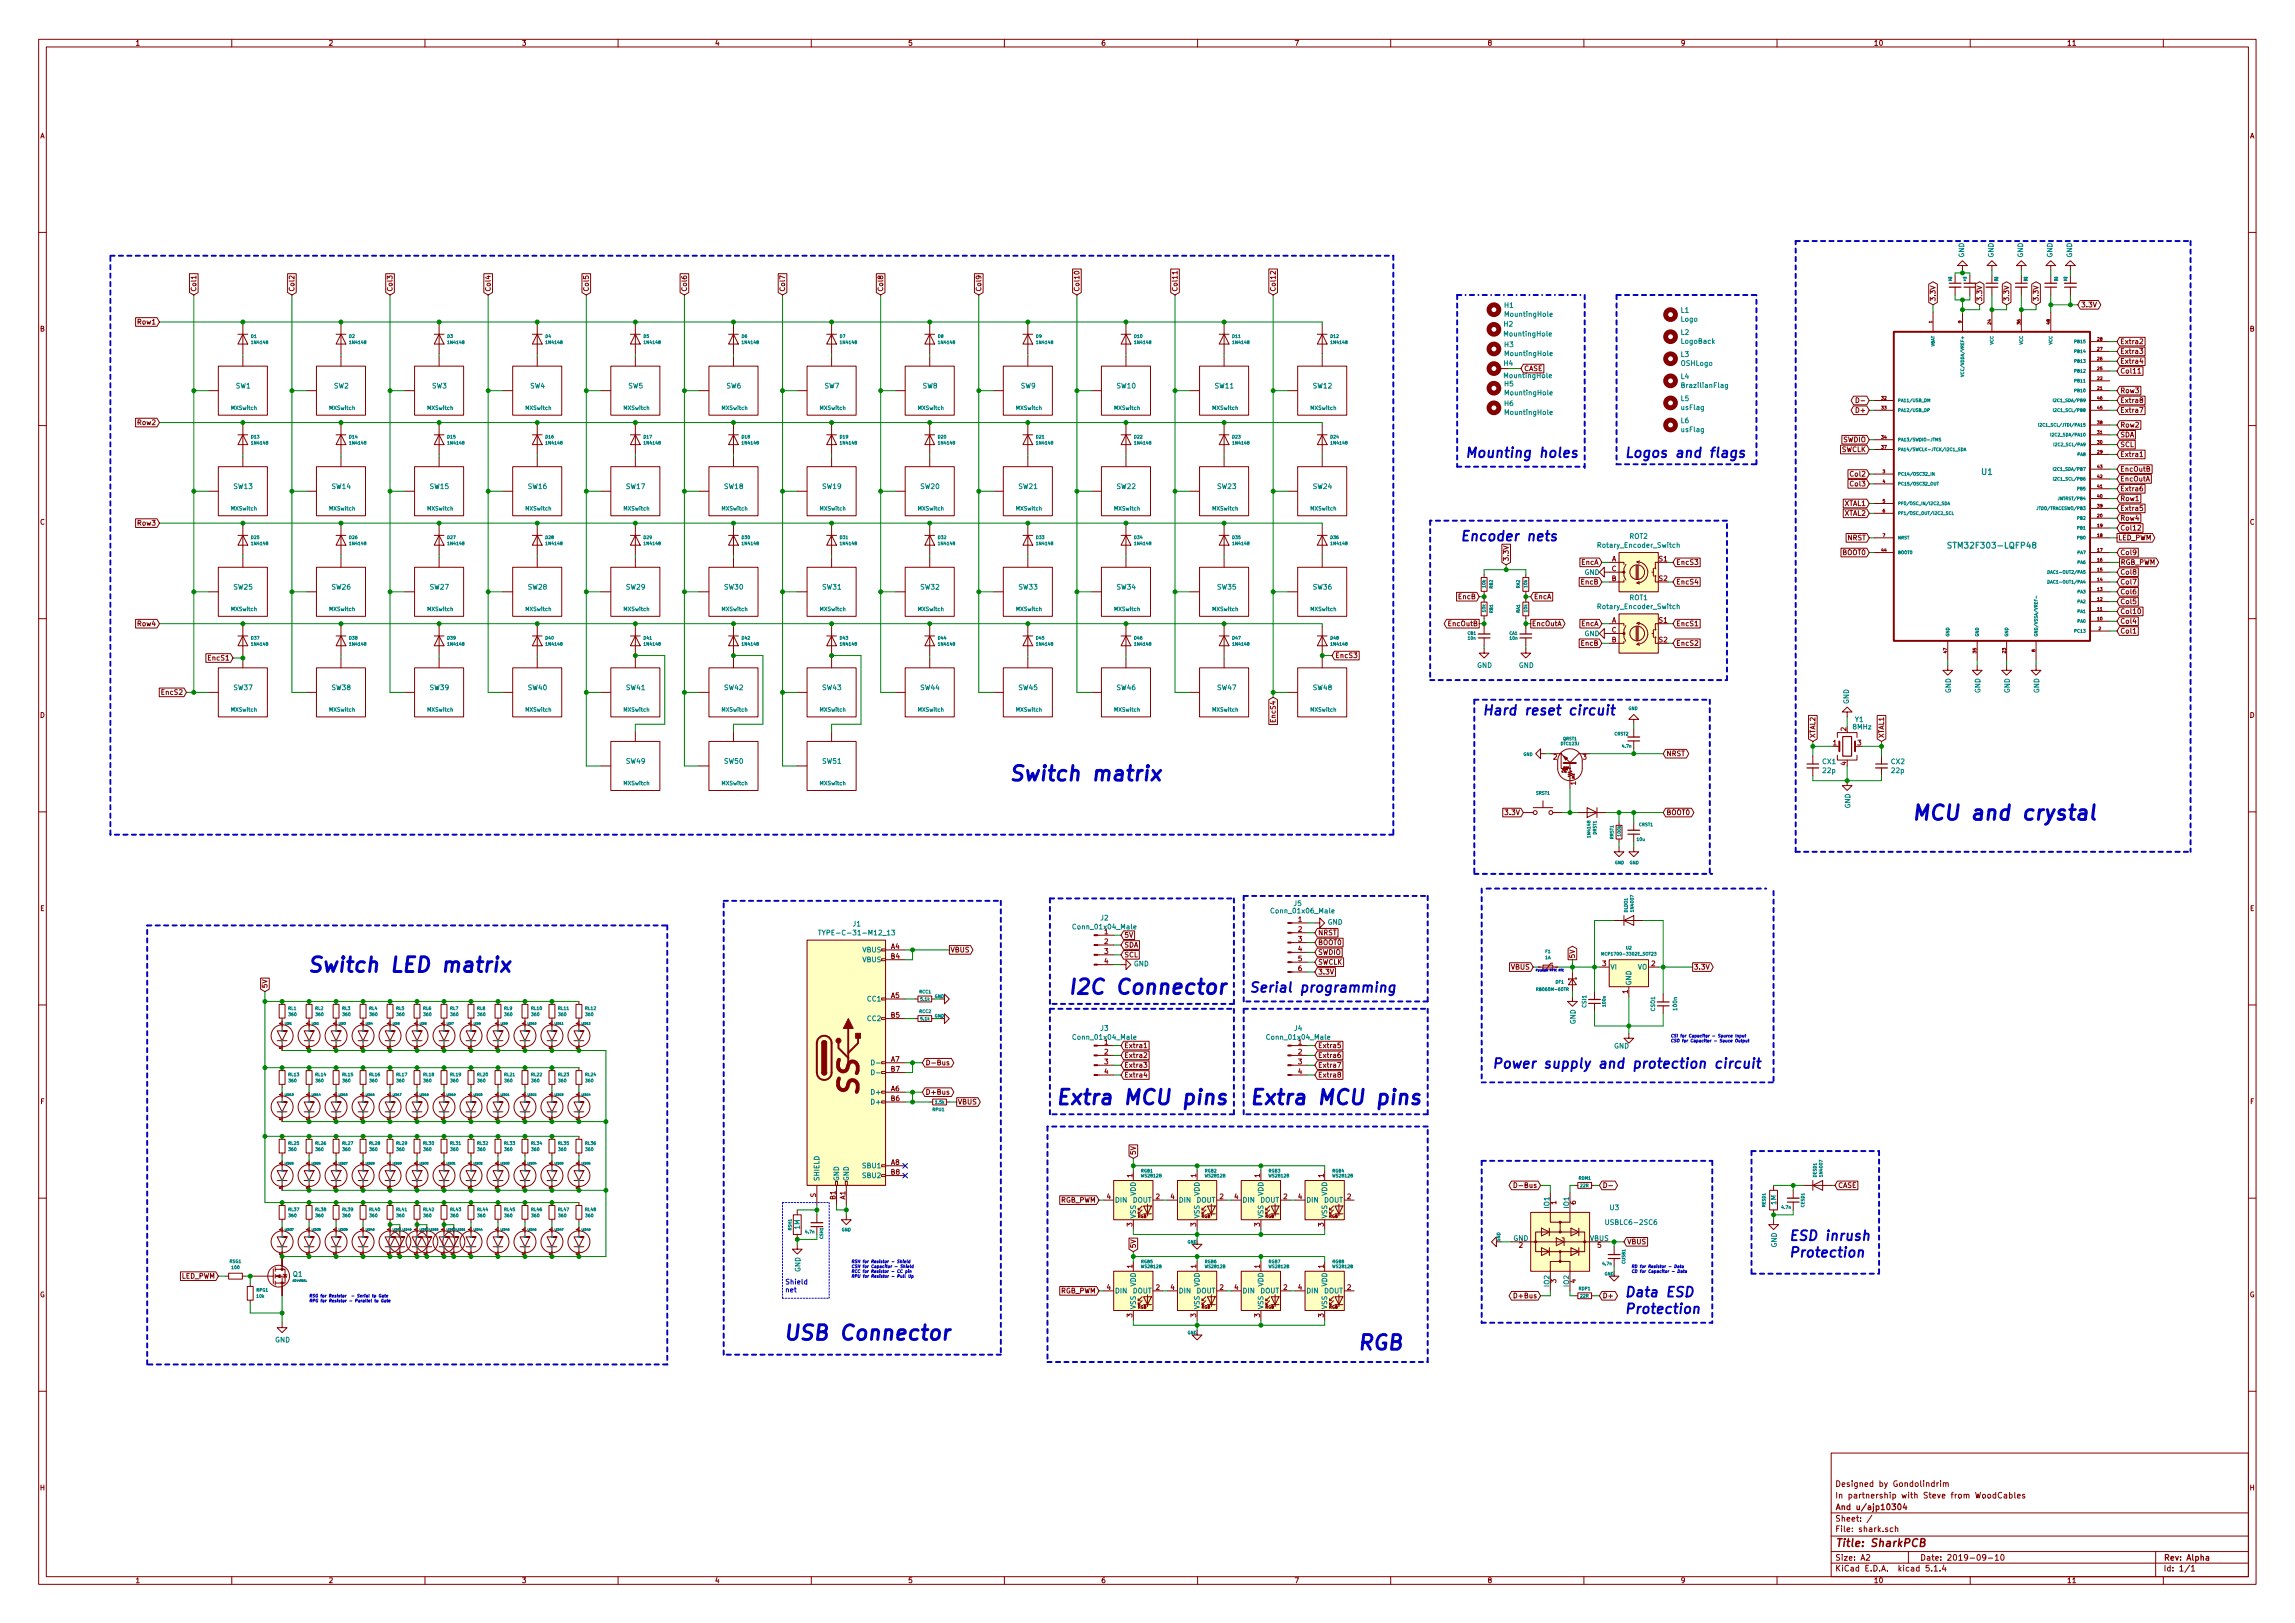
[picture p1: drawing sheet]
<svg xmlns="http://www.w3.org/2000/svg" width="594mm" height="420mm" viewBox="0 0 594 420" stroke-linecap="round" stroke-linejoin="round" font-family="sans-serif">
<defs><g id="words">
<text font-size="7.1" fill="#840000" x="222.3" y="283" transform="rotate(-90 222.3 283)">SS</text>
<g font-size="5.3" fill="#0000c2">
<text x="261" y="202.2">Switch matrix</text>
<text x="494.7" y="212.3">MCU and crystal</text>
<text x="79.4" y="251.7">Switch LED matrix</text>
<text x="276.2" y="257.4">I2C Connector</text>
<text x="273" y="286">Extra MCU pins</text>
<text x="323.2" y="286">Extra MCU pins</text>
<text x="202.6" y="347">USB Connector</text>
<text x="351.2" y="349.5">RGB</text>
</g>
<g font-size="3.5" fill="#0000c2">
<text x="379.1" y="118.5">Mounting holes</text>
<text x="420.4" y="118.5">Logos and flags</text>
<text x="377.8" y="140.1">Encoder nets</text>
<text x="383.5" y="185.2">Hard reset circuit</text>
<text x="323.2" y="256.9">Serial programming</text>
<text x="386.1" y="276.6">Power supply and protection circuit</text>
<text x="462.9" y="321.2">ESD inrush</text>
<text x="462.9" y="325.5">Protection</text>
<text x="420.4" y="335.8">Data ESD</text>
<text x="420.4" y="340.1">Protection</text>
</g>
<text font-size="2.8" fill="#840000" x="475" y="400.4">Title: SharkPCB</text>
<g font-size="2.1" fill="#008484">
<text x="513" y="122.9">U1</text>
<text x="505.4" y="142">STM32F303-LQFP48</text>
</g>
<g font-size="2.1" fill="#840000">
<text x="475" y="387.9">In partnership with Steve from WoodCables</text>
<text x="475" y="384.9">Designed by Gondolindrim</text>
<text x="475" y="393.9">Sheet: /</text>
<text x="475" y="390.9">And u/ajp10304</text>
<text x="475" y="396.6">File: shark.sch</text>
<text x="475" y="406.8">KiCad E.D.A. kicad 5.1.4</text>
<text x="475" y="404">Size: A2</text>
<text x="497" y="404">Date: 2019-09-10</text>
<text x="560" y="404">Rev: Alpha</text>
<text x="560" y="406.8">Id: 1/1</text>
</g>
<g font-size="1.8" fill="#840000">
<text x="35" y="11.8">1</text>
<text x="85" y="11.8">2</text>
<text x="135" y="11.8">3</text>
<text x="185" y="11.8">4</text>
<text x="235" y="11.8">5</text>
<text x="285" y="11.8">6</text>
<text x="335" y="11.8">7</text>
<text x="385" y="11.8">8</text>
<text x="435" y="11.8">9</text>
<text x="485" y="11.8">10</text>
<text x="535" y="11.8">11</text>
<text x="10.4" y="35.8">A</text>
<text x="582.4" y="35.8">A</text>
<text x="50.8" y="75.6" transform="rotate(-90 50.8 75.6)">Col1</text>
<text x="76.2" y="75.6" transform="rotate(-90 76.2 75.6)">Col2</text>
<text x="101.6" y="75.6" transform="rotate(-90 101.6 75.6)">Col3</text>
<text x="127" y="75.6" transform="rotate(-90 127 75.6)">Col4</text>
<text x="152.4" y="75.6" transform="rotate(-90 152.4 75.6)">Col5</text>
<text x="177.8" y="75.6" transform="rotate(-90 177.8 75.6)">Col6</text>
<text x="203.2" y="75.6" transform="rotate(-90 203.2 75.6)">Col7</text>
<text x="228.6" y="75.6" transform="rotate(-90 228.6 75.6)">Col8</text>
<text x="254" y="75.6" transform="rotate(-90 254 75.6)">Col9</text>
<text x="279.4" y="75.6" transform="rotate(-90 279.4 75.6)">Col10</text>
<text x="304.8" y="75.6" transform="rotate(-90 304.8 75.6)">Col11</text>
<text x="330.2" y="75.6" transform="rotate(-90 330.2 75.6)">Col12</text>
<text x="35.8" y="84">Row1</text>
<text x="501" y="78.1" transform="rotate(-90 501 78.1)">3.3V</text>
<text x="513.1" y="78.1" transform="rotate(-90 513.1 78.1)">3.3V</text>
<text x="520.1" y="78.1" transform="rotate(-90 520.1 78.1)">3.3V</text>
<text x="527.7" y="78.1" transform="rotate(-90 527.7 78.1)">3.3V</text>
<text x="538.6" y="79.5">3.3V</text>
<text x="10.4" y="85.8">B</text>
<text x="548.8" y="89.1">Extra2</text>
<text x="582.4" y="85.8">B</text>
<text x="548.8" y="94.1">Extra4</text>
<text x="548.8" y="91.6">Extra3</text>
<text x="394.5" y="96.1">CASE</text>
<text x="548.8" y="101.8">Row3</text>
<text x="548.8" y="96.7">Col11</text>
<text x="480.8" y="106.8">D+</text>
<text x="548.8" y="106.8">Extra7</text>
<text x="548.8" y="104.3">Extra8</text>
<text x="35.8" y="110">Row2</text>
<text x="548.8" y="113.2">SDA</text>
<text x="548.8" y="110.7">Row2</text>
<text x="476.6" y="117">SWCLK</text>
<text x="477.1" y="114.5">SWDIO</text>
<text x="548.8" y="115.7">SCL</text>
<text x="548.8" y="118.3">Extra1</text>
<text x="479.2" y="123.4">Col2</text>
<text x="479.2" y="125.9">Col3</text>
<text x="548.8" y="122.1">EncOutB</text>
<text x="548.8" y="124.6">EncOutA</text>
<text x="477.5" y="131">XTAL1</text>
<text x="548.8" y="129.7">Row1</text>
<text x="548.8" y="127.2">Extra6</text>
<text x="10.4" y="135.8">C</text>
<text x="35.8" y="136.1">Row3</text>
<text x="477.5" y="133.5">XTAL2</text>
<text x="548.8" y="137.3">Col12</text>
<text x="548.8" y="134.8">Row4</text>
<text x="548.8" y="132.2">Extra5</text>
<text x="582.4" y="135.8">C</text>
<text x="477" y="143.7">BOOT0</text>
<text x="478.3" y="139.9">NRST</text>
<text x="548.3" y="139.9">LED_PWM</text>
<text x="548.8" y="143.7">Col9</text>
<text x="390.5" y="145.4" transform="rotate(-90 390.5 145.4)">3.3V</text>
<text x="409.3" y="146.2">EncA</text>
<text x="417.2" y="145.3">A</text>
<text x="417.2" y="147.9">C</text>
<text x="429.5" y="145.3">S1</text>
<text x="433.9" y="146.2">EncS3</text>
<text x="548.8" y="148.8">Col8</text>
<text x="548.9" y="146.2">RGB_PWM</text>
<text x="377.6" y="155.1">EncB</text>
<text x="397" y="155.1">EncA</text>
<text x="409.3" y="151.3">EncB</text>
<text x="417.2" y="150.4">B</text>
<text x="429.5" y="150.4">S2</text>
<text x="433.9" y="151.3">EncS4</text>
<text x="548.8" y="151.3">Col7</text>
<text x="548.8" y="153.8">Col6</text>
<text x="417.2" y="161.2">A</text>
<text x="429.5" y="161.2">S1</text>
<text x="548.8" y="158.9">Col10</text>
<text x="548.8" y="156.4">Col5</text>
<text x="548.8" y="161.5">Col4</text>
<text x="35.8" y="162.1">Row4</text>
<text x="375.1" y="162.1">EncOutB</text>
<text x="396.5" y="162.1">EncOutA</text>
<text x="409.3" y="162.1">EncA</text>
<text x="409.3" y="167.2">EncB</text>
<text x="417.2" y="166.3">B</text>
<text x="417.2" y="163.7">C</text>
<text x="429.5" y="166.3">S2</text>
<text x="433.9" y="167.2">EncS2</text>
<text x="433.9" y="162.1">EncS1</text>
<text x="548.8" y="164">Col1</text>
<text x="54.1" y="171">EncS1</text>
<text x="345.6" y="170.3">EncS3</text>
<text x="42.1" y="179.9">EncS2</text>
<text x="10.4" y="185.8">D</text>
<text x="582.4" y="185.8">D</text>
<text x="330.2" y="186.7" transform="rotate(-90 330.2 186.7)">EncS4</text>
<text x="469.9" y="191.2" transform="rotate(-90 469.9 191.2)">XTAL2</text>
<text x="477.9" y="189.2" transform="rotate(-90 477.9 189.2)">2</text>
<text x="487.7" y="191.2" transform="rotate(-90 487.7 191.2)">XTAL1</text>
<text x="402.1" y="196.6">2</text>
<text x="409.7" y="196.6">3</text>
<text x="431.3" y="195.7">NRST</text>
<text x="474.5" y="193">1</text>
<text x="480.8" y="193">3</text>
<text x="407.9" y="203.2" transform="rotate(-90 407.9 203.2)">1</text>
<text x="477.9" y="198.1" transform="rotate(-90 477.9 198.1)">4</text>
<text x="389.9" y="211">3.3V</text>
<text x="431.3" y="211">BOOT0</text>
<text x="10.4" y="235.8">E</text>
<text x="336.1" y="238.7">1</text>
<text x="582.4" y="235.8">E</text>
<text x="230.7" y="245.7">A4</text>
<text x="285.9" y="241.9">1</text>
<text x="285.9" y="244.4">2</text>
<text x="291" y="242.7">5V</text>
<text x="291" y="245.3">SDA</text>
<text x="336.1" y="241.2">2</text>
<text x="336.1" y="243.8">3</text>
<text x="341.1" y="244.6">BOOT0</text>
<text x="341.1" y="242.1">NRST</text>
<text x="230.7" y="248.2">B4</text>
<text x="246" y="246.5">VBUS</text>
<text x="285.9" y="246.9">3</text>
<text x="285.9" y="249.5">4</text>
<text x="291" y="247.8">SCL</text>
<text x="336.1" y="246.3">4</text>
<text x="336.1" y="248.8">5</text>
<text x="336.1" y="251.4">6</text>
<text x="341.1" y="249.7">SWCLK</text>
<text x="341.1" y="247.2">SWDIO</text>
<text x="391.2" y="251">VBUS</text>
<text x="407.7" y="248.2" transform="rotate(-90 407.7 248.2)">5V</text>
<text x="414.8" y="250.1">3</text>
<text x="427.5" y="250.1">2</text>
<text x="438.4" y="251">3.3V</text>
<text x="69.2" y="255.9" transform="rotate(-90 69.2 255.9)">5V</text>
<text x="341.1" y="252.3">3.3V</text>
<text x="421.4" y="257.2" transform="rotate(-90 421.4 257.2)">1</text>
<text x="230.7" y="258.4">A5</text>
<text x="230.7" y="263.4">B5</text>
<text x="230.7" y="274.9">A7</text>
<text x="239.5" y="275.8">D-Bus</text>
<text x="285.9" y="270.4">1</text>
<text x="285.9" y="273">2</text>
<text x="285.9" y="275.5">3</text>
<text x="291" y="271.3">Extra1</text>
<text x="291" y="273.9">Extra2</text>
<text x="336.1" y="270.4">1</text>
<text x="336.1" y="273">2</text>
<text x="336.1" y="275.5">3</text>
<text x="341.1" y="271.3">Extra5</text>
<text x="341.1" y="273.9">Extra6</text>
<text x="230.7" y="277.4">B7</text>
<text x="285.9" y="278">4</text>
<text x="291" y="278.9">Extra4</text>
<text x="291" y="276.4">Extra3</text>
<text x="336.1" y="278">4</text>
<text x="341.1" y="278.9">Extra8</text>
<text x="341.1" y="276.4">Extra7</text>
<text x="10.5" y="285.8">F</text>
<text x="230.7" y="282.5">A6</text>
<text x="230.7" y="285">B6</text>
<text x="239.5" y="283.4">D+Bus</text>
<text x="247.9" y="285.9">VBUS</text>
<text x="582.5" y="285.8">F</text>
<text x="294" y="299.1" transform="rotate(-90 294 299.1)">5V</text>
<text x="230.7" y="301.5">A8</text>
<text x="230.7" y="304.1">B8</text>
<text x="293.1" y="304.8" transform="rotate(-90 293.1 304.8)">1</text>
<text x="309.6" y="304.8" transform="rotate(-90 309.6 304.8)">1</text>
<text x="326.1" y="304.8" transform="rotate(-90 326.1 304.8)">1</text>
<text x="342.6" y="304.8" transform="rotate(-90 342.6 304.8)">1</text>
<text x="211.2" y="310" transform="rotate(-90 211.2 310)">S</text>
<text x="216.3" y="310.5" transform="rotate(-90 216.3 310.5)">B1</text>
<text x="218.8" y="310.5" transform="rotate(-90 218.8 310.5)">A1</text>
<text x="274.4" y="311.3">RGB_PWM</text>
<text x="286.5" y="310.4">4</text>
<text x="299.2" y="310.4">2</text>
<text x="303" y="310.4">4</text>
<text x="315.7" y="310.4">2</text>
<text x="319.6" y="310.4">4</text>
<text x="332.3" y="310.4">2</text>
<text x="336.1" y="310.4">4</text>
<text x="348.8" y="310.4">2</text>
<text x="392.8" y="307.5">D-Bus</text>
<text x="402.8" y="311.8" transform="rotate(-90 402.8 311.8)">1</text>
<text x="407.9" y="311.8" transform="rotate(-90 407.9 311.8)">6</text>
<text x="475.8" y="307.5">CASE</text>
<text x="293.1" y="317.5" transform="rotate(-90 293.1 317.5)">3</text>
<text x="309.6" y="317.5" transform="rotate(-90 309.6 317.5)">3</text>
<text x="326.1" y="317.5" transform="rotate(-90 326.1 317.5)">3</text>
<text x="342.6" y="317.5" transform="rotate(-90 342.6 317.5)">3</text>
<text x="294" y="323.2" transform="rotate(-90 294 323.2)">5V</text>
<text x="393.2" y="323">2</text>
<text x="413.5" y="323">5</text>
<text x="421.2" y="322.1">VBUS</text>
<text x="293.1" y="328.3" transform="rotate(-90 293.1 328.3)">1</text>
<text x="309.6" y="328.3" transform="rotate(-90 309.6 328.3)">1</text>
<text x="326.1" y="328.3" transform="rotate(-90 326.1 328.3)">1</text>
<text x="342.6" y="328.3" transform="rotate(-90 342.6 328.3)">1</text>
<text x="10.3" y="335.8">G</text>
<text x="46.9" y="331">LED_PWM</text>
<text x="274.4" y="334.8">RGB_PWM</text>
<text x="286.5" y="333.9">4</text>
<text x="299.2" y="333.9">2</text>
<text x="303" y="333.9">4</text>
<text x="315.7" y="333.9">2</text>
<text x="319.6" y="333.9">4</text>
<text x="332.3" y="333.9">2</text>
<text x="336.1" y="333.9">4</text>
<text x="348.8" y="333.9">2</text>
<text x="402.8" y="332.1" transform="rotate(-90 402.8 332.1)">3</text>
<text x="407.9" y="332.1" transform="rotate(-90 407.9 332.1)">4</text>
<text x="582.3" y="335.8">G</text>
<text x="293.1" y="341" transform="rotate(-90 293.1 341)">3</text>
<text x="309.6" y="341" transform="rotate(-90 309.6 341)">3</text>
<text x="326.1" y="341" transform="rotate(-90 326.1 341)">3</text>
<text x="342.6" y="341" transform="rotate(-90 342.6 341)">3</text>
<text x="392.4" y="336.1">D+Bus</text>
<text x="414.8" y="336.1">D+</text>
<text x="10.4" y="385.8">H</text>
<text x="582.4" y="385.8">H</text>
<text x="35" y="409.8">1</text>
<text x="85" y="409.8">2</text>
<text x="135" y="409.8">3</text>
<text x="185" y="409.8">4</text>
<text x="235" y="409.8">5</text>
<text x="285" y="409.8">6</text>
<text x="335" y="409.8">7</text>
<text x="385" y="409.8">8</text>
<text x="435" y="409.8">9</text>
<text x="485" y="409.8">10</text>
<text x="535" y="409.8">11</text>
</g>
<g font-size="1.8" fill="#008484">
<text x="508.4" y="66.7" transform="rotate(-90 508.4 66.7)">GND</text>
<text x="516.1" y="66.7" transform="rotate(-90 516.1 66.7)">GND</text>
<text x="523.7" y="66.7" transform="rotate(-90 523.7 66.7)">GND</text>
<text x="531.3" y="66.7" transform="rotate(-90 531.3 66.7)">GND</text>
<text x="536.4" y="66.7" transform="rotate(-90 536.4 66.7)">GND</text>
<text x="389.5" y="79.7">H1</text>
<text x="389.8" y="82">MountingHole</text>
<text x="435.1" y="83.3">Logo</text>
<text x="435.2" y="81">L1</text>
<text x="389.3" y="84.5">H2</text>
<text x="389.5" y="89.9">H3</text>
<text x="389.6" y="87.1">MountingHole</text>
<text x="435.2" y="86.7">L2</text>
<text x="435.3" y="89">LogoBack</text>
<text x="389.3" y="94.7">H4</text>
<text x="389.8" y="92.2">MountingHole</text>
<text x="435.2" y="92.4">L3</text>
<text x="435.2" y="94.7">OSHLogo</text>
<text x="61.1" y="100.6">SW1</text>
<text x="86.5" y="100.6">SW2</text>
<text x="111.9" y="100.6">SW3</text>
<text x="137.3" y="100.6">SW4</text>
<text x="162.7" y="100.6">SW5</text>
<text x="188.1" y="100.6">SW6</text>
<text x="213.5" y="100.6">SW7</text>
<text x="238.9" y="100.6">SW8</text>
<text x="264.3" y="100.6">SW9</text>
<text x="289.1" y="100.6">SW10</text>
<text x="314.5" y="100.6">SW11</text>
<text x="339.9" y="100.6">SW12</text>
<text x="389.5" y="100">H5</text>
<text x="389.6" y="97.9">MountingHole</text>
<text x="435.2" y="98.1">L4</text>
<text x="435.8" y="100.4">BrazilianFlag</text>
<text x="389.5" y="105.1">H6</text>
<text x="389.8" y="102.3">MountingHole</text>
<text x="389.8" y="107.4">MountingHole</text>
<text x="435.2" y="103.8">L5</text>
<text x="435.3" y="106.1">usFlag</text>
<text x="435.2" y="109.5">L6</text>
<text x="435.3" y="111.9">usFlag</text>
<text x="60.5" y="126.6">SW13</text>
<text x="85.9" y="126.6">SW14</text>
<text x="111.3" y="126.6">SW15</text>
<text x="136.7" y="126.6">SW16</text>
<text x="162.1" y="126.6">SW17</text>
<text x="187.5" y="126.6">SW18</text>
<text x="212.9" y="126.6">SW19</text>
<text x="238.3" y="126.6">SW20</text>
<text x="263.7" y="126.6">SW21</text>
<text x="289.1" y="126.6">SW22</text>
<text x="315.2" y="126.6">SW23</text>
<text x="339.9" y="126.6">SW24</text>
<text x="414" y="141.8">Rotary_Encoder_Switch</text>
<text x="421.8" y="139.5">ROT2</text>
<text x="410.2" y="148.8">GND</text>
<text x="60.5" y="152.6">SW25</text>
<text x="85.9" y="152.6">SW26</text>
<text x="111.3" y="152.6">SW27</text>
<text x="136.7" y="152.6">SW28</text>
<text x="162.1" y="152.6">SW29</text>
<text x="187.5" y="152.6">SW30</text>
<text x="212.9" y="152.6">SW31</text>
<text x="238.3" y="152.6">SW32</text>
<text x="263.7" y="152.6">SW33</text>
<text x="289.1" y="152.6">SW34</text>
<text x="315.2" y="152.6">SW35</text>
<text x="339.9" y="152.6">SW36</text>
<text x="421.8" y="155.4">ROT1</text>
<text x="414" y="157.7">Rotary_Encoder_Switch</text>
<text x="410.2" y="164.7">GND</text>
<text x="382.3" y="172.9">GND</text>
<text x="393.1" y="172.9">GND</text>
<text x="60.5" y="178.7">SW37</text>
<text x="85.9" y="178.7">SW38</text>
<text x="111.3" y="178.7">SW39</text>
<text x="136.7" y="178.7">SW40</text>
<text x="162.1" y="178.7">SW41</text>
<text x="187.5" y="178.7">SW42</text>
<text x="212.9" y="178.7">SW43</text>
<text x="238.3" y="178.7">SW44</text>
<text x="263.7" y="178.7">SW45</text>
<text x="289.1" y="178.7">SW46</text>
<text x="315.2" y="178.7">SW47</text>
<text x="339.9" y="178.7">SW48</text>
<text x="505" y="179.5" transform="rotate(-90 505 179.5)">GND</text>
<text x="512.6" y="179.5" transform="rotate(-90 512.6 179.5)">GND</text>
<text x="520.2" y="179.5" transform="rotate(-90 520.2 179.5)">GND</text>
<text x="527.9" y="179.5" transform="rotate(-90 527.9 179.5)">GND</text>
<text x="478.6" y="182.3" transform="rotate(-90 478.6 182.3)">GND</text>
<text x="479.7" y="188.8">8MHz</text>
<text x="480.2" y="186.9">Y1</text>
<text x="162.1" y="197.7">SW49</text>
<text x="187.5" y="197.7">SW50</text>
<text x="212.9" y="197.7">SW51</text>
<text x="471.8" y="197.8">CX1</text>
<text x="489.6" y="197.8">CX2</text>
<text x="471.9" y="200.1">22p</text>
<text x="489.7" y="200.1">22p</text>
<text x="479" y="209.3" transform="rotate(-90 479 209.3)">GND</text>
<text x="220.8" y="239.8">J1</text>
<text x="284.9" y="238.3">J2</text>
<text x="329.5" y="236.4">Conn_01x06_Male</text>
<text x="334.9" y="234.5">J5</text>
<text x="343.7" y="239.4">GND</text>
<text x="213.8" y="242.1">TYPE-C-31-M12_13</text>
<text x="278.2" y="240.6">Conn_01x04_Male</text>
<text x="223.3" y="246.5">VBUS</text>
<text x="223.3" y="249.1">VBUS</text>
<text x="293.5" y="250.2">GND</text>
<text x="416.8" y="251">VI</text>
<text x="423.9" y="251">VO</text>
<text x="422.3" y="255.2" transform="rotate(-90 422.3 255.2)">GND</text>
<text x="224.7" y="259.2">CC1</text>
<text x="224.7" y="264.3">CC2</text>
<text x="278.2" y="269.2">Conn_01x04_Male</text>
<text x="284.9" y="266.8">J3</text>
<text x="328.4" y="269.2">Conn_01x04_Male</text>
<text x="335.1" y="266.8">J4</text>
<text x="407.8" y="265.2" transform="rotate(-90 407.8 265.2)">GND</text>
<text x="417.8" y="271.4">GND</text>
<text x="225.9" y="283.4">D+</text>
<text x="225.9" y="285.9">D+</text>
<text x="212.1" y="305.9" transform="rotate(-90 212.1 305.9)">SHIELD</text>
<text x="217.2" y="305.9" transform="rotate(-90 217.2 305.9)">GND</text>
<text x="219.7" y="305.9" transform="rotate(-90 219.7 305.9)">GND</text>
<text x="223.5" y="302.4">SBU1</text>
<text x="223.5" y="305">SBU2</text>
<text x="288.5" y="311.3">DIN</text>
<text x="293.2" y="311.3">DOUT</text>
<text x="294" y="309.6" transform="rotate(-90 294 309.6)">VDD</text>
<text x="305.1" y="311.3">DIN</text>
<text x="309.7" y="311.3">DOUT</text>
<text x="310.5" y="309.6" transform="rotate(-90 310.5 309.6)">VDD</text>
<text x="321.6" y="311.3">DIN</text>
<text x="326.2" y="311.3">DOUT</text>
<text x="327" y="309.6" transform="rotate(-90 327 309.6)">VDD</text>
<text x="338.1" y="311.3">DIN</text>
<text x="342.7" y="311.3">DOUT</text>
<text x="343.5" y="309.6" transform="rotate(-90 343.5 309.6)">VDD</text>
<text x="459.8" y="311.9" transform="rotate(-90 459.8 311.9)">1M</text>
<text x="294" y="315.5" transform="rotate(-90 294 315.5)">VSS</text>
<text x="310.5" y="315.5" transform="rotate(-90 310.5 315.5)">VSS</text>
<text x="327" y="315.5" transform="rotate(-90 327 315.5)">VSS</text>
<text x="343.5" y="315.5" transform="rotate(-90 343.5 315.5)">VSS</text>
<text x="401.1" y="312.7" transform="rotate(-90 401.1 312.7)">IO1</text>
<text x="406.1" y="312.7" transform="rotate(-90 406.1 312.7)">IO1</text>
<text x="416.2" y="317.1">USBLC6-2SC6</text>
<text x="416.8" y="313.3">U3</text>
<text x="207.1" y="318.2" transform="rotate(-90 207.1 318.2)">1M</text>
<text x="391.7" y="321.2">GND</text>
<text x="411.6" y="321.2">VBUS</text>
<text x="459.9" y="323" transform="rotate(-90 459.9 323)">GND</text>
<text x="207.2" y="329.3" transform="rotate(-90 207.2 329.3)">GND</text>
<text x="75.9" y="330.5">Q1</text>
<text x="288.5" y="334.8">DIN</text>
<text x="293.2" y="334.8">DOUT</text>
<text x="294" y="333.1" transform="rotate(-90 294 333.1)">VDD</text>
<text x="305.1" y="334.8">DIN</text>
<text x="309.7" y="334.8">DOUT</text>
<text x="310.5" y="333.1" transform="rotate(-90 310.5 333.1)">VDD</text>
<text x="321.6" y="334.8">DIN</text>
<text x="326.2" y="334.8">DOUT</text>
<text x="327" y="333.1" transform="rotate(-90 327 333.1)">VDD</text>
<text x="338.1" y="334.8">DIN</text>
<text x="342.7" y="334.8">DOUT</text>
<text x="343.5" y="333.1" transform="rotate(-90 343.5 333.1)">VDD</text>
<text x="401.1" y="333.1" transform="rotate(-90 401.1 333.1)">IO2</text>
<text x="406.1" y="333.1" transform="rotate(-90 406.1 333.1)">IO2</text>
<text x="294" y="339" transform="rotate(-90 294 339)">VSS</text>
<text x="310.5" y="339" transform="rotate(-90 310.5 339)">VSS</text>
<text x="327" y="339" transform="rotate(-90 327 339)">VSS</text>
<text x="343.5" y="339" transform="rotate(-90 343.5 339)">VSS</text>
<text x="71.2" y="347.5">GND</text>
</g>
<g font-size="1.8" fill="#0000c2">
<text x="203.2" y="332.5">Shield</text>
<text x="203.2" y="334.6">net</text>
</g>
<g font-size="1.4" fill="#008484">
<text x="59.9" y="106.1">MXSwitch</text>
<text x="85.3" y="106.1">MXSwitch</text>
<text x="110.7" y="106.1">MXSwitch</text>
<text x="136.1" y="106.1">MXSwitch</text>
<text x="161.5" y="106.1">MXSwitch</text>
<text x="186.9" y="106.1">MXSwitch</text>
<text x="212.3" y="106.1">MXSwitch</text>
<text x="237.7" y="106.1">MXSwitch</text>
<text x="263.1" y="106.1">MXSwitch</text>
<text x="288.5" y="106.1">MXSwitch</text>
<text x="313.9" y="106.1">MXSwitch</text>
<text x="339.3" y="106.1">MXSwitch</text>
<text x="59.9" y="132.1">MXSwitch</text>
<text x="85.3" y="132.1">MXSwitch</text>
<text x="110.7" y="132.1">MXSwitch</text>
<text x="136.1" y="132.1">MXSwitch</text>
<text x="161.5" y="132.1">MXSwitch</text>
<text x="186.9" y="132.1">MXSwitch</text>
<text x="212.3" y="132.1">MXSwitch</text>
<text x="237.7" y="132.1">MXSwitch</text>
<text x="263.1" y="132.1">MXSwitch</text>
<text x="288.5" y="132.1">MXSwitch</text>
<text x="313.9" y="132.1">MXSwitch</text>
<text x="339.3" y="132.1">MXSwitch</text>
<text x="59.9" y="158.2">MXSwitch</text>
<text x="85.3" y="158.2">MXSwitch</text>
<text x="110.7" y="158.2">MXSwitch</text>
<text x="136.1" y="158.2">MXSwitch</text>
<text x="161.5" y="158.2">MXSwitch</text>
<text x="186.9" y="158.2">MXSwitch</text>
<text x="212.3" y="158.2">MXSwitch</text>
<text x="237.7" y="158.2">MXSwitch</text>
<text x="263.1" y="158.2">MXSwitch</text>
<text x="288.5" y="158.2">MXSwitch</text>
<text x="313.9" y="158.2">MXSwitch</text>
<text x="339.3" y="158.2">MXSwitch</text>
<text x="59.9" y="184.2">MXSwitch</text>
<text x="85.3" y="184.2">MXSwitch</text>
<text x="110.7" y="184.2">MXSwitch</text>
<text x="136.1" y="184.2">MXSwitch</text>
<text x="161.5" y="184.2">MXSwitch</text>
<text x="186.9" y="184.2">MXSwitch</text>
<text x="212.3" y="184.2">MXSwitch</text>
<text x="237.7" y="184.2">MXSwitch</text>
<text x="263.1" y="184.2">MXSwitch</text>
<text x="288.5" y="184.2">MXSwitch</text>
<text x="313.9" y="184.2">MXSwitch</text>
<text x="339.3" y="184.2">MXSwitch</text>
<text x="161.5" y="203.3">MXSwitch</text>
<text x="186.9" y="203.3">MXSwitch</text>
<text x="212.3" y="203.3">MXSwitch</text>
<text x="410.6" y="260.8" transform="rotate(-90 410.6 260.8)">CSI1</text>
<text x="428.4" y="261.8" transform="rotate(-90 428.4 261.8)">CSO1</text>
<text x="434.1" y="261.5" transform="rotate(-90 434.1 261.5)">100n</text>
</g>
<g font-size="1.1" fill="#840000">
<text x="500.2" y="83.7" transform="rotate(-90 500.2 83.7)">1</text>
<text x="507.8" y="83.7" transform="rotate(-90 507.8 83.7)">9</text>
<text x="515.4" y="84" transform="rotate(-90 515.4 84)">24</text>
<text x="523" y="84" transform="rotate(-90 523 84)">36</text>
<text x="530.6" y="84" transform="rotate(-90 530.6 84)">48</text>
<text x="543" y="88.2">28</text>
<text x="543" y="95.8">25</text>
<text x="543" y="93.3">26</text>
<text x="543" y="90.7">27</text>
<text x="543" y="100.9">21</text>
<text x="543" y="98.4">22</text>
<text x="487.1" y="103.4">32</text>
<text x="487.1" y="106">33</text>
<text x="543" y="106">45</text>
<text x="543" y="103.4">46</text>
<text x="487.1" y="113.6">34</text>
<text x="543" y="112.3">31</text>
<text x="543" y="109.8">38</text>
<text x="487.1" y="116.1">37</text>
<text x="543" y="117.4">29</text>
<text x="543" y="114.9">30</text>
<text x="487.4" y="122.5">3</text>
<text x="487.4" y="125">4</text>
<text x="543" y="123.8">42</text>
<text x="543" y="121.2">43</text>
<text x="487.4" y="130.1">5</text>
<text x="543" y="131.4">39</text>
<text x="543" y="128.8">40</text>
<text x="543" y="126.3">41</text>
<text x="487.4" y="132.7">6</text>
<text x="543" y="136.5">19</text>
<text x="543" y="133.9">20</text>
<text x="487.1" y="142.8">44</text>
<text x="487.4" y="139">7</text>
<text x="543" y="142.8">17</text>
<text x="543" y="139">18</text>
<text x="543" y="147.9">15</text>
<text x="543" y="145.4">16</text>
<text x="543" y="155.5">12</text>
<text x="543" y="153">13</text>
<text x="543" y="150.4">14</text>
<text x="543" y="160.6">10</text>
<text x="543" y="158.1">11</text>
<text x="543.3" y="163.1">2</text>
<text x="504" y="169.1" transform="rotate(-90 504 169.1)">47</text>
<text x="511.6" y="169.1" transform="rotate(-90 511.6 169.1)">35</text>
<text x="519.2" y="169.1" transform="rotate(-90 519.2 169.1)">23</text>
<text x="526.8" y="168.7" transform="rotate(-90 526.8 168.7)">8</text>
<text x="294.5" y="315.3">RGB</text>
<text x="311" y="315.3">RGB</text>
<text x="327.5" y="315.3">RGB</text>
<text x="344" y="315.3">RGB</text>
<text x="294.5" y="338.8">RGB</text>
<text x="311" y="338.8">RGB</text>
<text x="327.5" y="338.8">RGB</text>
<text x="344" y="338.8">RGB</text>
</g>
<g font-size="1.1" fill="#008484">
<text x="65" y="87.4">D1</text>
<text x="65.3" y="89">1N4148</text>
<text x="90.4" y="87.4">D2</text>
<text x="90.7" y="89">1N4148</text>
<text x="115.8" y="87.4">D3</text>
<text x="116.1" y="89">1N4148</text>
<text x="141.2" y="87.4">D4</text>
<text x="141.5" y="89">1N4148</text>
<text x="166.6" y="87.4">D5</text>
<text x="166.9" y="89">1N4148</text>
<text x="192" y="87.4">D6</text>
<text x="192.3" y="89">1N4148</text>
<text x="217.4" y="87.4">D7</text>
<text x="217.7" y="89">1N4148</text>
<text x="242.8" y="87.4">D8</text>
<text x="243.1" y="89">1N4148</text>
<text x="268.2" y="87.4">D9</text>
<text x="268.5" y="89">1N4148</text>
<text x="293.7" y="87.4">D10</text>
<text x="293.9" y="89">1N4148</text>
<text x="319.1" y="87.4">D11</text>
<text x="319.3" y="89">1N4148</text>
<text x="344.5" y="87.4">D12</text>
<text x="344.7" y="89">1N4148</text>
<text x="500.8" y="89.9" transform="rotate(-90 500.8 89.9)">VBAT</text>
<text x="516" y="89.2" transform="rotate(-90 516 89.2)">VCC</text>
<text x="523.6" y="89.2" transform="rotate(-90 523.6 89.2)">VCC</text>
<text x="531.2" y="89.2" transform="rotate(-90 531.2 89.2)">VCC</text>
<text x="537.3" y="88.8">PB15</text>
<text x="537.3" y="93.9">PB13</text>
<text x="537.3" y="91.4">PB14</text>
<text x="508.4" y="96.5" transform="rotate(-90 508.4 96.5)">VCC/VDDA/VREF+</text>
<text x="537.3" y="101.5">PB10</text>
<text x="537.3" y="99">PB11</text>
<text x="537.3" y="96.4">PB12</text>
<text x="491.2" y="104.1">PA11/USB_DM</text>
<text x="491.2" y="106.6">PA12/USB_DP</text>
<text x="532.3" y="104.1">I2C1_SDA/PB9</text>
<text x="532.4" y="106.6">I2C1_SCL/PB8</text>
<text x="65.1" y="113.5">D13</text>
<text x="90.5" y="113.5">D14</text>
<text x="115.9" y="113.5">D15</text>
<text x="141.3" y="113.5">D16</text>
<text x="166.7" y="113.5">D17</text>
<text x="192.1" y="113.5">D18</text>
<text x="217.5" y="113.5">D19</text>
<text x="242.9" y="113.5">D20</text>
<text x="268.3" y="113.5">D21</text>
<text x="293.7" y="113.5">D22</text>
<text x="319.1" y="113.5">D23</text>
<text x="344.5" y="113.5">D24</text>
<text x="529.2" y="110.4">I2C1_SCL/JTDI/PA15</text>
<text x="531.7" y="112.9">I2C2_SDA/PA10</text>
<text x="65.3" y="115.1">1N4148</text>
<text x="90.7" y="115.1">1N4148</text>
<text x="116.1" y="115.1">1N4148</text>
<text x="141.5" y="115.1">1N4148</text>
<text x="166.9" y="115.1">1N4148</text>
<text x="192.3" y="115.1">1N4148</text>
<text x="217.7" y="115.1">1N4148</text>
<text x="243.1" y="115.1">1N4148</text>
<text x="268.5" y="115.1">1N4148</text>
<text x="293.9" y="115.1">1N4148</text>
<text x="319.3" y="115.1">1N4148</text>
<text x="344.7" y="115.1">1N4148</text>
<text x="491.2" y="114.2">PA13/SWDIO-JTMS</text>
<text x="491.2" y="116.8">PA14/SWCLK-JTCK/I2C1_SDA</text>
<text x="532.4" y="115.5">I2C2_SCL/PA9</text>
<text x="537.9" y="118">PA8</text>
<text x="491.2" y="123.1">PC14/OSC32_IN</text>
<text x="491.2" y="125.6">PC15/OSC32_OUT</text>
<text x="532.3" y="121.8">I2C1_SDA/PB7</text>
<text x="532.4" y="124.4">I2C1_SCL/PB6</text>
<text x="491.2" y="130.7">PF0/OSC_IN/I2C2_SDA</text>
<text x="527.9" y="132">JTDO/TRACESWO/PB3</text>
<text x="533.3" y="129.5">JNTRST/PB4</text>
<text x="537.9" y="126.9">PB5</text>
<text x="491.2" y="133.3">PF1/OSC_OUT/I2C2_SCL</text>
<text x="537.9" y="137.1">PB1</text>
<text x="537.9" y="134.5">PB2</text>
<text x="65.1" y="139.5">D25</text>
<text x="65.3" y="141.1">1N4148</text>
<text x="90.5" y="139.5">D26</text>
<text x="90.7" y="141.1">1N4148</text>
<text x="115.9" y="139.5">D27</text>
<text x="116.1" y="141.1">1N4148</text>
<text x="141.3" y="139.5">D28</text>
<text x="141.5" y="141.1">1N4148</text>
<text x="166.7" y="139.5">D29</text>
<text x="166.9" y="141.1">1N4148</text>
<text x="192.1" y="139.5">D30</text>
<text x="192.3" y="141.1">1N4148</text>
<text x="217.5" y="139.5">D31</text>
<text x="217.7" y="141.1">1N4148</text>
<text x="242.9" y="139.5">D32</text>
<text x="243.1" y="141.1">1N4148</text>
<text x="268.3" y="139.5">D33</text>
<text x="268.5" y="141.1">1N4148</text>
<text x="293.7" y="139.5">D34</text>
<text x="293.9" y="141.1">1N4148</text>
<text x="319.1" y="139.5">D35</text>
<text x="319.3" y="141.1">1N4148</text>
<text x="344.5" y="139.5">D36</text>
<text x="344.7" y="141.1">1N4148</text>
<text x="491.2" y="143.4">BOOT0</text>
<text x="491.2" y="139.6">NRST</text>
<text x="537.9" y="143.4">PA7</text>
<text x="537.9" y="139.6">PB0</text>
<text x="531.3" y="148.5">DAC1-OUT2/PA5</text>
<text x="537.9" y="146">PA6</text>
<text x="384.5" y="152.1" transform="rotate(-90 384.5 152.1)">10k</text>
<text x="386.4" y="152.3" transform="rotate(-90 386.4 152.3)">RB2</text>
<text x="393.4" y="152.3" transform="rotate(-90 393.4 152.3)">RA2</text>
<text x="395.3" y="152.1" transform="rotate(-90 395.3 152.1)">10k</text>
<text x="531.3" y="151">DAC1-OUT1/PA4</text>
<text x="537.9" y="153.6">PA3</text>
<text x="384.5" y="158.4" transform="rotate(-90 384.5 158.4)">10k</text>
<text x="386.4" y="158.7" transform="rotate(-90 386.4 158.7)">RB1</text>
<text x="393.4" y="158.6" transform="rotate(-90 393.4 158.6)">RA1</text>
<text x="395.3" y="158.4" transform="rotate(-90 395.3 158.4)">10k</text>
<text x="537.9" y="161.2">PA0</text>
<text x="537.9" y="158.7">PA1</text>
<text x="537.9" y="156.1">PA2</text>
<text x="65.1" y="165.5">D37</text>
<text x="65.3" y="167.1">1N4148</text>
<text x="90.5" y="165.5">D38</text>
<text x="90.7" y="167.1">1N4148</text>
<text x="115.9" y="165.5">D39</text>
<text x="116.1" y="167.1">1N4148</text>
<text x="141.3" y="165.5">D40</text>
<text x="141.5" y="167.1">1N4148</text>
<text x="166.7" y="165.5">D41</text>
<text x="166.9" y="167.1">1N4148</text>
<text x="192.1" y="165.5">D42</text>
<text x="192.3" y="167.1">1N4148</text>
<text x="217.5" y="165.5">D43</text>
<text x="217.7" y="167.1">1N4148</text>
<text x="242.9" y="165.5">D44</text>
<text x="243.1" y="167.1">1N4148</text>
<text x="268.3" y="165.5">D45</text>
<text x="268.5" y="167.1">1N4148</text>
<text x="293.7" y="165.5">D46</text>
<text x="293.9" y="167.1">1N4148</text>
<text x="319.1" y="165.5">D47</text>
<text x="319.3" y="167.1">1N4148</text>
<text x="344.5" y="165.5">D48</text>
<text x="344.7" y="167.1">1N4148</text>
<text x="379.9" y="164.3">CB1</text>
<text x="380.1" y="165.6">10n</text>
<text x="390.7" y="164.3">CA1</text>
<text x="390.9" y="165.6">10n</text>
<text x="504.6" y="164.9" transform="rotate(-90 504.6 164.9)">GND</text>
<text x="512.2" y="164.9" transform="rotate(-90 512.2 164.9)">GND</text>
<text x="519.8" y="164.9" transform="rotate(-90 519.8 164.9)">GND</text>
<text x="527.4" y="164.9" transform="rotate(-90 527.4 164.9)">GND/VSSA/VREF-</text>
<text x="537.3" y="163.7">PC13</text>
<text x="421.5" y="183.8">GND</text>
<text x="404.6" y="191.6">QRST1</text>
<text x="417.9" y="190.4">CRST2</text>
<text x="394.3" y="195.7">GND</text>
<text x="404.1" y="192.9">DTC123J</text>
<text x="420" y="193.5">4.7n</text>
<text x="397.7" y="205.7">SRST1</text>
<text x="424.3" y="213.9">CRST1</text>
<text x="411.7" y="216.6" transform="rotate(-90 411.7 216.6)">1N4148</text>
<text x="413.2" y="216.1" transform="rotate(-90 413.2 216.1)">DRST1</text>
<text x="417.6" y="217.2" transform="rotate(-90 417.6 217.2)">RRST1</text>
<text x="419.5" y="216.4" transform="rotate(-90 419.5 216.4)">100k</text>
<text x="423.8" y="217.7">10u</text>
<text x="418" y="223.7">GND</text>
<text x="421.8" y="223.7">GND</text>
<text x="421.3" y="236.2" transform="rotate(-90 421.3 236.2)">DLDO1</text>
<text x="422.9" y="235.8" transform="rotate(-90 422.9 235.8)">1N4007</text>
<text x="421" y="245.8">U2</text>
<text x="400" y="248.3">1A</text>
<text x="400" y="246.7">F1</text>
<text x="415.4" y="247.3">MCP1700-3302E_SOT23</text>
<text x="238" y="257.1">RCC1</text>
<text x="398.2" y="256.5">RB060M-60TR</text>
<text x="402.7" y="254.6">DF1</text>
<text x="74.6" y="261.4">RL1</text>
<text x="74.8" y="263">360</text>
<text x="81.6" y="261.4">RL2</text>
<text x="81.8" y="263">360</text>
<text x="88.6" y="261.4">RL3</text>
<text x="88.8" y="263">360</text>
<text x="95.6" y="261.4">RL4</text>
<text x="95.8" y="263">360</text>
<text x="102.6" y="261.4">RL5</text>
<text x="102.7" y="263">360</text>
<text x="109.6" y="261.4">RL6</text>
<text x="109.7" y="263">360</text>
<text x="116.5" y="261.4">RL7</text>
<text x="116.7" y="263">360</text>
<text x="123.5" y="261.4">RL8</text>
<text x="123.7" y="263">360</text>
<text x="130.5" y="261.4">RL9</text>
<text x="130.7" y="263">360</text>
<text x="137.6" y="261.4">RL10</text>
<text x="137.7" y="263">360</text>
<text x="144.6" y="261.4">RL11</text>
<text x="144.7" y="263">360</text>
<text x="151.5" y="261.4">RL12</text>
<text x="151.6" y="263">360</text>
<text x="238" y="262.2">RCC2</text>
<text x="238.4" y="259">5.1k</text>
<text x="415.6" y="260.5" transform="rotate(-90 415.6 260.5)">100n</text>
<text x="238.4" y="264.1">5.1k</text>
<text x="74.7" y="278.6">RL13</text>
<text x="74.8" y="280.2">360</text>
<text x="81.7" y="278.6">RL14</text>
<text x="81.8" y="280.2">360</text>
<text x="88.7" y="278.6">RL15</text>
<text x="88.8" y="280.2">360</text>
<text x="95.7" y="278.6">RL16</text>
<text x="95.8" y="280.2">360</text>
<text x="102.6" y="278.6">RL17</text>
<text x="102.7" y="280.2">360</text>
<text x="109.6" y="278.6">RL18</text>
<text x="109.7" y="280.2">360</text>
<text x="116.6" y="278.6">RL19</text>
<text x="116.7" y="280.2">360</text>
<text x="123.6" y="278.6">RL20</text>
<text x="123.7" y="280.2">360</text>
<text x="130.6" y="278.6">RL21</text>
<text x="130.7" y="280.2">360</text>
<text x="137.6" y="278.6">RL22</text>
<text x="137.7" y="280.2">360</text>
<text x="144.6" y="278.6">RL23</text>
<text x="144.7" y="280.2">360</text>
<text x="151.5" y="278.6">RL24</text>
<text x="151.6" y="280.2">360</text>
<text x="241.5" y="287.6">RPU1</text>
<text x="242.2" y="285.7">1.5k</text>
<text x="74.7" y="296.4">RL25</text>
<text x="74.8" y="297.9">360</text>
<text x="81.7" y="296.4">RL26</text>
<text x="81.8" y="297.9">360</text>
<text x="88.7" y="296.4">RL27</text>
<text x="88.8" y="297.9">360</text>
<text x="95.7" y="296.4">RL28</text>
<text x="95.8" y="297.9">360</text>
<text x="102.6" y="296.4">RL29</text>
<text x="102.7" y="297.9">360</text>
<text x="109.6" y="296.4">RL30</text>
<text x="109.7" y="297.9">360</text>
<text x="116.6" y="296.4">RL31</text>
<text x="116.7" y="297.9">360</text>
<text x="123.6" y="296.4">RL32</text>
<text x="123.7" y="297.9">360</text>
<text x="130.6" y="296.4">RL33</text>
<text x="130.7" y="297.9">360</text>
<text x="137.6" y="296.4">RL34</text>
<text x="137.7" y="297.9">360</text>
<text x="144.6" y="296.4">RL35</text>
<text x="144.7" y="297.9">360</text>
<text x="151.5" y="296.4">RL36</text>
<text x="151.6" y="297.9">360</text>
<text x="295.4" y="303.5">RGB1</text>
<text x="295.6" y="304.8">WS2812B</text>
<text x="311.9" y="303.5">RGB2</text>
<text x="312.1" y="304.8">WS2812B</text>
<text x="328.4" y="303.5">RGB3</text>
<text x="328.6" y="304.8">WS2812B</text>
<text x="344.9" y="303.5">RGB4</text>
<text x="345.1" y="304.8">WS2812B</text>
<text x="408.7" y="305.4">RDM1</text>
<text x="470.2" y="304.7" transform="rotate(-90 470.2 304.7)">DESD1</text>
<text x="471.8" y="304.4" transform="rotate(-90 471.8 304.4)">1N4007</text>
<text x="409.1" y="307.3">22R</text>
<text x="74.7" y="313.5">RL37</text>
<text x="74.8" y="315.1">360</text>
<text x="81.7" y="313.5">RL38</text>
<text x="81.8" y="315.1">360</text>
<text x="88.7" y="313.5">RL39</text>
<text x="88.8" y="315.1">360</text>
<text x="95.7" y="313.5">RL40</text>
<text x="95.8" y="315.1">360</text>
<text x="102.6" y="313.5">RL41</text>
<text x="102.7" y="315.1">360</text>
<text x="109.6" y="313.5">RL42</text>
<text x="109.7" y="315.1">360</text>
<text x="116.6" y="313.5">RL43</text>
<text x="116.7" y="315.1">360</text>
<text x="123.6" y="313.5">RL44</text>
<text x="123.7" y="315.1">360</text>
<text x="130.6" y="313.5">RL45</text>
<text x="130.7" y="315.1">360</text>
<text x="137.6" y="313.5">RL46</text>
<text x="137.7" y="315.1">360</text>
<text x="144.6" y="313.5">RL47</text>
<text x="144.7" y="315.1">360</text>
<text x="151.5" y="313.5">RL48</text>
<text x="151.6" y="315.1">360</text>
<text x="457" y="312.4" transform="rotate(-90 457 312.4)">RESD1</text>
<text x="461.3" y="312.9">4.7n</text>
<text x="467.1" y="312.5" transform="rotate(-90 467.1 312.5)">CESD1</text>
<text x="204.9" y="318.4" transform="rotate(-90 204.9 318.4)">RSH1</text>
<text x="208.5" y="319.3">4.7n</text>
<text x="213.1" y="320.7" transform="rotate(-90 213.1 320.7)">CSH1</text>
<text x="217.9" y="318.7">GND</text>
<text x="307.4" y="321.9">GND</text>
<text x="388.3" y="321.4" transform="rotate(-90 388.3 321.4)">GND</text>
<text x="59.5" y="326.9">RSG1</text>
<text x="60" y="328.5">100</text>
<text x="295.4" y="327">RGB5</text>
<text x="295.6" y="328.3">WS2812B</text>
<text x="311.9" y="327">RGB6</text>
<text x="312.1" y="328.3">WS2812B</text>
<text x="328.4" y="327">RGB7</text>
<text x="328.6" y="328.3">WS2812B</text>
<text x="344.9" y="327">RGB8</text>
<text x="345.1" y="328.3">WS2812B</text>
<text x="414.9" y="327.5">4.7n</text>
<text x="420.7" y="327.1" transform="rotate(-90 420.7 327.1)">CUSB1</text>
<text x="66.4" y="334.4">RPG1</text>
<text x="66.5" y="335.9">10k</text>
<text x="408.7" y="334">RDP1</text>
<text x="409.1" y="335.9">22R</text>
<text x="415.3" y="330.2">GND</text>
<text x="307.4" y="345.4">GND</text>
</g>
<g font-size="1.1" fill="#008400">
<text x="242" y="263.4">GND</text>
<text x="242" y="258.3">GND</text>
</g>
<g font-size="1.1" fill="#0000c2">
<text x="432.4" y="268.5">CSI for Capacitor - Source Input</text>
<text x="432.4" y="269.8">CSO for Capacitor - Souce Output</text>
<text x="220.3" y="327">RSH for Resistor - Shield</text>
<text x="220.3" y="328.2">CSH for Capacitor - Shield</text>
<text x="220.3" y="329.5">RCC for Resistor - CC pin</text>
<text x="422.3" y="328.2">RD for Resistor - Data</text>
<text x="422.3" y="329.5">CD for Capacitor - Data</text>
<text x="80" y="335.9">RSG for Resistor - Serial to Gate</text>
<text x="220.3" y="330.8">RPU for Resistor - Pull Up</text>
<text x="80" y="337.1">RPG for Resistor - Parallel to Gate</text>
</g>
<g font-size=".7" fill="#840000">
<text x="404.3" y="200">47k</text>
<text x="407.5" y="201.5" transform="rotate(-90 407.5 201.5)">2k2</text>
<text x="72.8" y="265.2" transform="rotate(-90 72.8 265.2)">A</text>
<text x="79.8" y="265.2" transform="rotate(-90 79.8 265.2)">A</text>
<text x="86.8" y="265.2" transform="rotate(-90 86.8 265.2)">A</text>
<text x="93.8" y="265.2" transform="rotate(-90 93.8 265.2)">A</text>
<text x="100.8" y="265.2" transform="rotate(-90 100.8 265.2)">A</text>
<text x="107.7" y="265.2" transform="rotate(-90 107.7 265.2)">A</text>
<text x="114.7" y="265.2" transform="rotate(-90 114.7 265.2)">A</text>
<text x="121.7" y="265.2" transform="rotate(-90 121.7 265.2)">A</text>
<text x="128.7" y="265.2" transform="rotate(-90 128.7 265.2)">A</text>
<text x="135.7" y="265.2" transform="rotate(-90 135.7 265.2)">A</text>
<text x="142.7" y="265.2" transform="rotate(-90 142.7 265.2)">A</text>
<text x="149.7" y="265.2" transform="rotate(-90 149.7 265.2)">A</text>
<text x="72.8" y="271.6" transform="rotate(-90 72.8 271.6)">K</text>
<text x="79.8" y="271.6" transform="rotate(-90 79.8 271.6)">K</text>
<text x="86.8" y="271.6" transform="rotate(-90 86.8 271.6)">K</text>
<text x="93.8" y="271.6" transform="rotate(-90 93.8 271.6)">K</text>
<text x="100.8" y="271.6" transform="rotate(-90 100.8 271.6)">K</text>
<text x="107.7" y="271.6" transform="rotate(-90 107.7 271.6)">K</text>
<text x="114.7" y="271.6" transform="rotate(-90 114.7 271.6)">K</text>
<text x="121.7" y="271.6" transform="rotate(-90 121.7 271.6)">K</text>
<text x="128.7" y="271.6" transform="rotate(-90 128.7 271.6)">K</text>
<text x="135.7" y="271.6" transform="rotate(-90 135.7 271.6)">K</text>
<text x="142.7" y="271.6" transform="rotate(-90 142.7 271.6)">K</text>
<text x="149.7" y="271.6" transform="rotate(-90 149.7 271.6)">K</text>
<text x="72.8" y="283.6" transform="rotate(-90 72.8 283.6)">A</text>
<text x="79.8" y="283.6" transform="rotate(-90 79.8 283.6)">A</text>
<text x="86.8" y="283.6" transform="rotate(-90 86.8 283.6)">A</text>
<text x="93.8" y="283.6" transform="rotate(-90 93.8 283.6)">A</text>
<text x="100.8" y="283.6" transform="rotate(-90 100.8 283.6)">A</text>
<text x="107.7" y="283.6" transform="rotate(-90 107.7 283.6)">A</text>
<text x="114.7" y="283.6" transform="rotate(-90 114.7 283.6)">A</text>
<text x="121.7" y="283.6" transform="rotate(-90 121.7 283.6)">A</text>
<text x="128.7" y="283.6" transform="rotate(-90 128.7 283.6)">A</text>
<text x="135.7" y="283.6" transform="rotate(-90 135.7 283.6)">A</text>
<text x="142.7" y="283.6" transform="rotate(-90 142.7 283.6)">A</text>
<text x="149.7" y="283.6" transform="rotate(-90 149.7 283.6)">A</text>
<text x="72.8" y="290" transform="rotate(-90 72.8 290)">K</text>
<text x="79.8" y="290" transform="rotate(-90 79.8 290)">K</text>
<text x="86.8" y="290" transform="rotate(-90 86.8 290)">K</text>
<text x="93.8" y="290" transform="rotate(-90 93.8 290)">K</text>
<text x="100.8" y="290" transform="rotate(-90 100.8 290)">K</text>
<text x="107.7" y="290" transform="rotate(-90 107.7 290)">K</text>
<text x="114.7" y="290" transform="rotate(-90 114.7 290)">K</text>
<text x="121.7" y="290" transform="rotate(-90 121.7 290)">K</text>
<text x="128.7" y="290" transform="rotate(-90 128.7 290)">K</text>
<text x="135.7" y="290" transform="rotate(-90 135.7 290)">K</text>
<text x="142.7" y="290" transform="rotate(-90 142.7 290)">K</text>
<text x="149.7" y="290" transform="rotate(-90 149.7 290)">K</text>
<text x="72.8" y="301.4" transform="rotate(-90 72.8 301.4)">A</text>
<text x="79.8" y="301.4" transform="rotate(-90 79.8 301.4)">A</text>
<text x="86.8" y="301.4" transform="rotate(-90 86.8 301.4)">A</text>
<text x="93.8" y="301.4" transform="rotate(-90 93.8 301.4)">A</text>
<text x="100.8" y="301.4" transform="rotate(-90 100.8 301.4)">A</text>
<text x="107.7" y="301.4" transform="rotate(-90 107.7 301.4)">A</text>
<text x="114.7" y="301.4" transform="rotate(-90 114.7 301.4)">A</text>
<text x="121.7" y="301.4" transform="rotate(-90 121.7 301.4)">A</text>
<text x="128.7" y="301.4" transform="rotate(-90 128.7 301.4)">A</text>
<text x="135.7" y="301.4" transform="rotate(-90 135.7 301.4)">A</text>
<text x="142.7" y="301.4" transform="rotate(-90 142.7 301.4)">A</text>
<text x="149.7" y="301.4" transform="rotate(-90 149.7 301.4)">A</text>
<text x="72.8" y="307.8" transform="rotate(-90 72.8 307.8)">K</text>
<text x="79.8" y="307.8" transform="rotate(-90 79.8 307.8)">K</text>
<text x="86.8" y="307.8" transform="rotate(-90 86.8 307.8)">K</text>
<text x="93.8" y="307.8" transform="rotate(-90 93.8 307.8)">K</text>
<text x="100.8" y="307.8" transform="rotate(-90 100.8 307.8)">K</text>
<text x="107.7" y="307.8" transform="rotate(-90 107.7 307.8)">K</text>
<text x="114.7" y="307.8" transform="rotate(-90 114.7 307.8)">K</text>
<text x="121.7" y="307.8" transform="rotate(-90 121.7 307.8)">K</text>
<text x="128.7" y="307.8" transform="rotate(-90 128.7 307.8)">K</text>
<text x="135.7" y="307.8" transform="rotate(-90 135.7 307.8)">K</text>
<text x="142.7" y="307.8" transform="rotate(-90 142.7 307.8)">K</text>
<text x="149.7" y="307.8" transform="rotate(-90 149.7 307.8)">K</text>
<text x="72.8" y="318.6" transform="rotate(-90 72.8 318.6)">A</text>
<text x="79.8" y="318.6" transform="rotate(-90 79.8 318.6)">A</text>
<text x="86.8" y="318.6" transform="rotate(-90 86.8 318.6)">A</text>
<text x="93.8" y="318.6" transform="rotate(-90 93.8 318.6)">A</text>
<text x="100.8" y="318.6" transform="rotate(-90 100.8 318.6)">A</text>
<text x="107.7" y="318.6" transform="rotate(-90 107.7 318.6)">A</text>
<text x="114.7" y="318.6" transform="rotate(-90 114.7 318.6)">A</text>
<text x="121.7" y="318.6" transform="rotate(-90 121.7 318.6)">A</text>
<text x="128.7" y="318.6" transform="rotate(-90 128.7 318.6)">A</text>
<text x="135.7" y="318.6" transform="rotate(-90 135.7 318.6)">A</text>
<text x="142.7" y="318.6" transform="rotate(-90 142.7 318.6)">A</text>
<text x="149.7" y="318.6" transform="rotate(-90 149.7 318.6)">A</text>
<text x="72.8" y="324.9" transform="rotate(-90 72.8 324.9)">K</text>
<text x="79.8" y="324.9" transform="rotate(-90 79.8 324.9)">K</text>
<text x="86.8" y="324.9" transform="rotate(-90 86.8 324.9)">K</text>
<text x="93.8" y="324.9" transform="rotate(-90 93.8 324.9)">K</text>
<text x="100.8" y="324.9" transform="rotate(-90 100.8 324.9)">K</text>
<text x="103.3" y="324.9" transform="rotate(-90 103.3 324.9)">K</text>
<text x="107.7" y="324.9" transform="rotate(-90 107.7 324.9)">K</text>
<text x="110.3" y="324.9" transform="rotate(-90 110.3 324.9)">K</text>
<text x="114.7" y="324.9" transform="rotate(-90 114.7 324.9)">K</text>
<text x="117.3" y="324.9" transform="rotate(-90 117.3 324.9)">K</text>
<text x="121.7" y="324.9" transform="rotate(-90 121.7 324.9)">K</text>
<text x="128.7" y="324.9" transform="rotate(-90 128.7 324.9)">K</text>
<text x="135.7" y="324.9" transform="rotate(-90 135.7 324.9)">K</text>
<text x="142.7" y="324.9" transform="rotate(-90 142.7 324.9)">K</text>
<text x="149.7" y="324.9" transform="rotate(-90 149.7 324.9)">K</text>
</g>
<text font-size=".7" fill="#0000c2" x="397.5" y="251.4">Polyfuse PPTC RTC</text>
<g font-size=".7" fill="#008484">
<text x="73.3" y="269.7" transform="rotate(-90 73.3 269.7)">K</text>
<text x="73.3" y="267.1" transform="rotate(-90 73.3 267.1)">A</text>
<text x="73.7" y="265.2">LED1</text>
<text x="80.3" y="269.7" transform="rotate(-90 80.3 269.7)">K</text>
<text x="80.3" y="267.1" transform="rotate(-90 80.3 267.1)">A</text>
<text x="80.7" y="265.2">LED2</text>
<text x="87.2" y="269.7" transform="rotate(-90 87.2 269.7)">K</text>
<text x="87.2" y="267.1" transform="rotate(-90 87.2 267.1)">A</text>
<text x="87.7" y="265.2">LED3</text>
<text x="94.2" y="269.7" transform="rotate(-90 94.2 269.7)">K</text>
<text x="94.2" y="267.1" transform="rotate(-90 94.2 267.1)">A</text>
<text x="94.7" y="265.2">LED4</text>
<text x="101.2" y="269.7" transform="rotate(-90 101.2 269.7)">K</text>
<text x="101.2" y="267.1" transform="rotate(-90 101.2 267.1)">A</text>
<text x="101.7" y="265.2">LED5</text>
<text x="108.2" y="269.7" transform="rotate(-90 108.2 269.7)">K</text>
<text x="108.2" y="267.1" transform="rotate(-90 108.2 267.1)">A</text>
<text x="108.7" y="265.2">LED6</text>
<text x="115.2" y="269.7" transform="rotate(-90 115.2 269.7)">K</text>
<text x="115.2" y="267.1" transform="rotate(-90 115.2 267.1)">A</text>
<text x="115.6" y="265.2">LED7</text>
<text x="122.2" y="269.7" transform="rotate(-90 122.2 269.7)">K</text>
<text x="122.2" y="267.1" transform="rotate(-90 122.2 267.1)">A</text>
<text x="122.6" y="265.2">LED8</text>
<text x="129.2" y="269.7" transform="rotate(-90 129.2 269.7)">K</text>
<text x="129.2" y="267.1" transform="rotate(-90 129.2 267.1)">A</text>
<text x="129.6" y="265.2">LED9</text>
<text x="136.1" y="269.7" transform="rotate(-90 136.1 269.7)">K</text>
<text x="136.1" y="267.1" transform="rotate(-90 136.1 267.1)">A</text>
<text x="136.6" y="265.2">LED10</text>
<text x="143.1" y="269.7" transform="rotate(-90 143.1 269.7)">K</text>
<text x="143.1" y="267.1" transform="rotate(-90 143.1 267.1)">A</text>
<text x="143.6" y="265.2">LED11</text>
<text x="150.1" y="269.7" transform="rotate(-90 150.1 269.7)">K</text>
<text x="150.1" y="267.1" transform="rotate(-90 150.1 267.1)">A</text>
<text x="150.6" y="265.2">LED12</text>
<text x="73.3" y="285.5" transform="rotate(-90 73.3 285.5)">A</text>
<text x="73.8" y="283.7">LED13</text>
<text x="80.3" y="285.5" transform="rotate(-90 80.3 285.5)">A</text>
<text x="80.7" y="283.7">LED14</text>
<text x="87.2" y="285.5" transform="rotate(-90 87.2 285.5)">A</text>
<text x="87.7" y="283.7">LED15</text>
<text x="94.2" y="285.5" transform="rotate(-90 94.2 285.5)">A</text>
<text x="94.7" y="283.7">LED16</text>
<text x="101.2" y="285.5" transform="rotate(-90 101.2 285.5)">A</text>
<text x="101.7" y="283.7">LED17</text>
<text x="108.2" y="285.5" transform="rotate(-90 108.2 285.5)">A</text>
<text x="108.7" y="283.7">LED18</text>
<text x="115.2" y="285.5" transform="rotate(-90 115.2 285.5)">A</text>
<text x="115.7" y="283.7">LED19</text>
<text x="122.2" y="285.5" transform="rotate(-90 122.2 285.5)">A</text>
<text x="122.7" y="283.7">LED20</text>
<text x="129.2" y="285.5" transform="rotate(-90 129.2 285.5)">A</text>
<text x="129.6" y="283.7">LED21</text>
<text x="136.1" y="285.5" transform="rotate(-90 136.1 285.5)">A</text>
<text x="136.6" y="283.7">LED22</text>
<text x="143.1" y="285.5" transform="rotate(-90 143.1 285.5)">A</text>
<text x="143.6" y="283.7">LED23</text>
<text x="150.1" y="285.5" transform="rotate(-90 150.1 285.5)">A</text>
<text x="150.6" y="283.7">LED24</text>
<text x="73.3" y="288.1" transform="rotate(-90 73.3 288.1)">K</text>
<text x="80.3" y="288.1" transform="rotate(-90 80.3 288.1)">K</text>
<text x="87.2" y="288.1" transform="rotate(-90 87.2 288.1)">K</text>
<text x="94.2" y="288.1" transform="rotate(-90 94.2 288.1)">K</text>
<text x="101.2" y="288.1" transform="rotate(-90 101.2 288.1)">K</text>
<text x="108.2" y="288.1" transform="rotate(-90 108.2 288.1)">K</text>
<text x="115.2" y="288.1" transform="rotate(-90 115.2 288.1)">K</text>
<text x="122.2" y="288.1" transform="rotate(-90 122.2 288.1)">K</text>
<text x="129.2" y="288.1" transform="rotate(-90 129.2 288.1)">K</text>
<text x="136.1" y="288.1" transform="rotate(-90 136.1 288.1)">K</text>
<text x="143.1" y="288.1" transform="rotate(-90 143.1 288.1)">K</text>
<text x="150.1" y="288.1" transform="rotate(-90 150.1 288.1)">K</text>
<text x="73.3" y="305.9" transform="rotate(-90 73.3 305.9)">K</text>
<text x="73.3" y="303.3" transform="rotate(-90 73.3 303.3)">A</text>
<text x="73.8" y="301.4">LED25</text>
<text x="80.3" y="305.9" transform="rotate(-90 80.3 305.9)">K</text>
<text x="80.3" y="303.3" transform="rotate(-90 80.3 303.3)">A</text>
<text x="80.7" y="301.4">LED26</text>
<text x="87.2" y="305.9" transform="rotate(-90 87.2 305.9)">K</text>
<text x="87.2" y="303.3" transform="rotate(-90 87.2 303.3)">A</text>
<text x="87.7" y="301.4">LED27</text>
<text x="94.2" y="305.9" transform="rotate(-90 94.2 305.9)">K</text>
<text x="94.2" y="303.3" transform="rotate(-90 94.2 303.3)">A</text>
<text x="94.7" y="301.4">LED28</text>
<text x="101.2" y="305.9" transform="rotate(-90 101.2 305.9)">K</text>
<text x="101.2" y="303.3" transform="rotate(-90 101.2 303.3)">A</text>
<text x="101.7" y="301.4">LED29</text>
<text x="108.2" y="305.9" transform="rotate(-90 108.2 305.9)">K</text>
<text x="108.2" y="303.3" transform="rotate(-90 108.2 303.3)">A</text>
<text x="108.7" y="301.4">LED30</text>
<text x="115.2" y="305.9" transform="rotate(-90 115.2 305.9)">K</text>
<text x="115.2" y="303.3" transform="rotate(-90 115.2 303.3)">A</text>
<text x="115.7" y="301.4">LED31</text>
<text x="122.2" y="305.9" transform="rotate(-90 122.2 305.9)">K</text>
<text x="122.2" y="303.3" transform="rotate(-90 122.2 303.3)">A</text>
<text x="122.7" y="301.4">LED32</text>
<text x="129.2" y="305.9" transform="rotate(-90 129.2 305.9)">K</text>
<text x="129.2" y="303.3" transform="rotate(-90 129.2 303.3)">A</text>
<text x="129.6" y="301.4">LED33</text>
<text x="136.1" y="305.9" transform="rotate(-90 136.1 305.9)">K</text>
<text x="136.1" y="303.3" transform="rotate(-90 136.1 303.3)">A</text>
<text x="136.6" y="301.4">LED34</text>
<text x="143.1" y="305.9" transform="rotate(-90 143.1 305.9)">K</text>
<text x="143.1" y="303.3" transform="rotate(-90 143.1 303.3)">A</text>
<text x="143.6" y="301.4">LED35</text>
<text x="150.1" y="305.9" transform="rotate(-90 150.1 305.9)">K</text>
<text x="150.1" y="303.3" transform="rotate(-90 150.1 303.3)">A</text>
<text x="150.6" y="301.4">LED36</text>
<text x="73.3" y="323" transform="rotate(-90 73.3 323)">K</text>
<text x="73.3" y="320.5" transform="rotate(-90 73.3 320.5)">A</text>
<text x="73.8" y="318.6">LED37</text>
<text x="80.3" y="323" transform="rotate(-90 80.3 323)">K</text>
<text x="80.3" y="320.5" transform="rotate(-90 80.3 320.5)">A</text>
<text x="80.7" y="318.6">LED38</text>
<text x="87.2" y="323" transform="rotate(-90 87.2 323)">K</text>
<text x="87.2" y="320.5" transform="rotate(-90 87.2 320.5)">A</text>
<text x="87.7" y="318.6">LED39</text>
<text x="94.2" y="323" transform="rotate(-90 94.2 323)">K</text>
<text x="94.2" y="320.5" transform="rotate(-90 94.2 320.5)">A</text>
<text x="94.7" y="318.6">LED40</text>
<text x="101.2" y="323" transform="rotate(-90 101.2 323)">K</text>
<text x="101.2" y="320.5" transform="rotate(-90 101.2 320.5)">A</text>
<text x="101.7" y="318.6">LED41 LED49</text>
<text x="103.3" y="318.6" transform="rotate(-90 103.3 318.6)">A</text>
<text x="103.8" y="323" transform="rotate(-90 103.8 323)">K</text>
<text x="103.8" y="320.5" transform="rotate(-90 103.8 320.5)">A</text>
<text x="108.2" y="323" transform="rotate(-90 108.2 323)">K</text>
<text x="108.2" y="320.5" transform="rotate(-90 108.2 320.5)">A</text>
<text x="108.7" y="318.6">LED42 LED50</text>
<text x="110.3" y="318.6" transform="rotate(-90 110.3 318.6)">A</text>
<text x="110.7" y="323" transform="rotate(-90 110.7 323)">K</text>
<text x="110.7" y="320.5" transform="rotate(-90 110.7 320.5)">A</text>
<text x="115.2" y="323" transform="rotate(-90 115.2 323)">K</text>
<text x="115.2" y="320.5" transform="rotate(-90 115.2 320.5)">A</text>
<text x="115.7" y="318.6">LED43 LED51</text>
<text x="117.3" y="318.6" transform="rotate(-90 117.3 318.6)">A</text>
<text x="117.7" y="323" transform="rotate(-90 117.7 323)">K</text>
<text x="117.7" y="320.5" transform="rotate(-90 117.7 320.5)">A</text>
<text x="122.2" y="323" transform="rotate(-90 122.2 323)">K</text>
<text x="122.2" y="320.5" transform="rotate(-90 122.2 320.5)">A</text>
<text x="122.7" y="318.6">LED44</text>
<text x="129.2" y="323" transform="rotate(-90 129.2 323)">K</text>
<text x="129.2" y="320.5" transform="rotate(-90 129.2 320.5)">A</text>
<text x="129.6" y="318.6">LED45</text>
<text x="136.1" y="323" transform="rotate(-90 136.1 323)">K</text>
<text x="136.1" y="320.5" transform="rotate(-90 136.1 320.5)">A</text>
<text x="136.6" y="318.6">LED46</text>
<text x="143.1" y="323" transform="rotate(-90 143.1 323)">K</text>
<text x="143.1" y="320.5" transform="rotate(-90 143.1 320.5)">A</text>
<text x="143.6" y="318.6">LED47</text>
<text x="150.1" y="323" transform="rotate(-90 150.1 323)">K</text>
<text x="150.1" y="320.5" transform="rotate(-90 150.1 320.5)">A</text>
<text x="150.6" y="318.6">LED48</text>
<text x="75.8" y="331.8">AO4406AL</text>
</g>
<g font-size=".4" fill="#008484">
<text x="504.4" y="72.1">CVB5</text>
<text x="504.5" y="72.7">10n</text>
<text x="508.2" y="72">CVB4</text>
<text x="508.4" y="72.7">1u</text>
<text x="516.3" y="72.1">CVB2</text>
<text x="516.4" y="72.7">100n</text>
<text x="523.9" y="72.1">CVB3</text>
<text x="524" y="72.7">100n</text>
<text x="531.8" y="72">CVB1</text>
<text x="531.9" y="72.7">100n</text>
<text x="534.2" y="72">CVB6</text>
<text x="534.3" y="72.7">4.7u</text>
</g>
</g></defs>
<g fill="none" stroke="#840000" stroke-width=".26">
<path d="M10 10.2h574v400h-574zM12 12.2h570v396h-570zM60 10.2v2M110 10.2v2M160 10.2v2M210 10.2v2M260 10.2v2M310 10.2v2M360 10.2v2M410 10.2v2M460 10.2v2M510 10.2v2"/>
<path d="M536.5 11.8h.8M560 10.2v2M10 60.2h2M49 70.9h2.3v4.8l-1.1 .7-1.2-.7zM50.7 71.4v.8M74.4 70.9h2.3v4.8l-1.1 .7-1.2-.7zM99.8 70.9h2.3v4.8l-1.1 .7-1.2-.7zM125.2 70.9h2.3v4.8l-1.1 .7-1.2-.7zM150.6 70.9h2.3v4.8l-1.1 .7-1.2-.7zM176 70.9h2.3v4.8l-1.1 .7-1.2-.7zM201.4 70.9h2.3v4.8l-1.1 .7-1.2-.7zM226.8 70.9h2.3v4.8l-1.1 .7-1.2-.7z"/>
<path d="M252.2 70.9h2.3v4.8l-1.1 .7-1.2-.7zM277.6 69.6h2.3v6.1l-1.1 .7-1.2-.7zM278.2 70.3a.61 .61 0 0 1 .7-.1 .61 .61 0 0 1 .4 .6 .76 .76 0 0 1-1.2-.3zM303 69.6h2.3v6.1l-1.1 .7-1.2-.7zM304.7 70.6h-1.2l.3 .4M304.7 70.2v.8M328.4 69.6h2.3v6.1l-1.1 .7-1.2-.7zM330.1 70.2v.8l-.9-.8-.3 .3 .1 .5M499.3 73.6l1.1-.7 1.1 .7v4.7l-1.1 .6-1.1-.6zM506.1 71.3v2M506.1 74.3v2.1M508 68.7h1.3l-1.3-1.2-1.3 1.2h1.3v1.3"/>
<path d="M509.9 71.3v2M509.9 74.3v2.1M511.3 73.6l1.1-.7 1.2 .7v4.7l-1.2 .6-1.1-.6zM515.6 68.7h1.3l-1.3-1.2-1.3 1.2h1.3v1.3M515.6 71.3v2M515.6 74.3v2.1M518.3 73.6l1.1-.7 1.1 .7v4.7l-1.1 .6-1.1-.6zM523.2 68.7h1.3l-1.3-1.2-1.2 1.2h1.2v1.3M523.2 71.3v2M523.2 74.3v2.1M525.9 73.6l1.1-.7 1.2 .7v4.7l-1.2 .6-1.1-.6zM530.9 68.7h1.2l-1.2-1.2-1.3 1.2h1.3v1.3"/>
<path d="M530.9 71.3v2M530.9 74.3v2.1M535.9 68.7h1.3l-1.3-1.2-1.2 1.2h1.2v1.3M535.9 71.3v2M535.9 74.3v2.1M538.5 77.8h4.7l.6 1.1-.6 1.1h-4.7l-.7-1.1zM582 60.2h2M35.1 82.2h5.5l.7 1.2-.7 1.1h-5.5zM56.5 94.8h12.7v12.7h-12.7zM61.6 86.5h2.5M62.9 86.5l1.2 2.6h-2.5zM62.9 84v7.6"/>
<path d="M62.9 92.2v2.6M81.9 94.8h12.7v12.7h-12.7zM87 86.5h2.5M88.3 86.5l1.2 2.6h-2.5zM88.3 84v7.6M88.3 92.2v2.6M107.3 94.8h12.7v12.7h-12.7zM112.4 86.5h2.5M113.7 86.5l1.2 2.6h-2.5zM113.7 84v7.6M113.7 92.2v2.6M132.7 94.8h12.7v12.7h-12.7z"/>
<path d="M137.8 86.5h2.5M139.1 86.5l1.2 2.6h-2.5zM139.1 84v7.6M139.1 92.2v2.6M158.1 94.8h12.7v12.7h-12.7zM163.2 86.5h2.5M164.5 86.5l1.2 2.6h-2.5zM164.5 84v7.6M164.5 92.2v2.6M183.5 94.8h12.7v12.7h-12.7zM188.6 86.5h2.5M189.9 86.5l1.2 2.6h-2.5z"/>
<path d="M189.9 84v7.6M189.9 92.2v2.6M208.9 94.8h12.7v12.7h-12.7zM214 86.5h2.5M215.3 86.5l1.2 2.6h-2.5zM215.3 84v7.6M215.3 92.2v2.6M234.3 94.8h12.7v12.7h-12.7zM239.4 86.5h2.5M240.7 86.5l1.2 2.6h-2.5zM240.7 84v7.6M240.7 92.2v2.6"/>
<path d="M259.7 94.8h12.7v12.7h-12.7zM264.8 86.5h2.5M266.1 86.5l1.2 2.6h-2.5zM266.1 84v7.6M266.1 92.2v2.6M285.1 94.8h12.7v12.7h-12.7zM290.2 86.5h2.5M291.5 86.5l1.2 2.6h-2.5zM291.5 84v7.6M291.5 92.2v2.6M310.5 94.8h12.7v12.7h-12.7zM315.6 86.5h2.5"/>
<path d="M316.9 86.5l1.2 2.6h-2.5zM316.9 84v7.6M316.9 92.2v2.6M335.9 94.8h12.7v12.7h-12.7zM341 86.5h2.5M342.3 86.5l1.2 2.6h-2.5zM342.3 84v7.6M342.3 92.2v2.6M388 95.4h2.5M394.3 94.3h5.3v2.2h-5.3l-.6-1.1zM500.4 80.8v5.1M508 80.8v5.1"/>
<path d="M515.6 80.8v5.1M523.2 80.8v5.1M530.9 80.8v5.1M541 98.6h5.1M541 96.1h5.1M541 93.5h5.1M541 91h5.1M541 88.4h5.1M548.6 92.4h6.7v2.2h-6.7l-.6-1.1zM548.6 87.3h6.7v2.3h-6.7l-.6-1.2zM548.6 89.9h6.7v2.2h-6.7l-.6-1.1zM548.6 94.9h6.1v2.3h-6.1l-.6-1.1z"/>
<path d="M553.4 95.7l.3-.4v1.3M553.4 96.6h.7M553.9 90.3h.8l-.5 .4 .4 .2v.5h-.7M553.9 87.9l.5-.2 .3 .4-.8 .9h.8M554.2 92.8l-.3 .8h.8M554.5 93.2v.9M10 110.2h2M35.1 108.3h5.5l.7 1.1-.7 1.1h-5.5zM54 101.1h2.5M61.6 112.6h2.5M62.9 112.6l1.2 2.5h-2.5zM62.9 110v7.6"/>
<path d="M62.9 118.3v2.5M79.4 101.1h2.5M87 112.6h2.5M88.3 112.6l1.2 2.5h-2.5zM88.3 110v7.6M88.3 118.3v2.5M104.8 101.1h2.5M112.4 112.6h2.5M113.7 112.6l1.2 2.5h-2.5zM113.7 110v7.6M113.7 118.3v2.5M130.2 101.1h2.5"/>
<path d="M137.8 112.6h2.5M139.1 112.6l1.2 2.5h-2.5zM139.1 110v7.6M139.1 118.3v2.5M155.6 101.1h2.5M163.2 112.6h2.5M164.5 112.6l1.2 2.5h-2.5zM164.5 110v7.6M164.5 118.3v2.5M181 101.1h2.5M188.6 112.6h2.5M189.9 112.6l1.2 2.5h-2.5z"/>
<path d="M189.9 110v7.6M189.9 118.3v2.5M206.4 101.1h2.5M214 112.6h2.5M215.3 112.6l1.2 2.5h-2.5zM215.3 110v7.6M215.3 118.3v2.5M231.8 101.1h2.5M239.4 112.6h2.5M240.7 112.6l1.2 2.5h-2.5zM240.7 110v7.6M240.7 118.3v2.5"/>
<path d="M257.2 101.1h2.5M264.8 112.6h2.5M266.1 112.6l1.2 2.5h-2.5zM266.1 110v7.6M266.1 118.3v2.5M282.6 101.1h2.5M290.2 112.6h2.5M291.5 112.6l1.2 2.5h-2.5zM291.5 110v7.6M291.5 118.3v2.5M308 101.1h2.5M315.6 112.6h2.5"/>
<path d="M316.9 112.6l1.2 2.5h-2.5zM316.9 110v7.6M316.9 118.3v2.5M333.4 101.1h2.5M341 112.6h2.5M342.3 112.6l1.2 2.5h-2.5zM342.3 110v7.6M342.3 118.3v2.5M476.4 115.3h6.8l.7 1.1-.7 1.1h-6.8zM476.8 112.7h6.4l.7 1.1-.7 1.2h-6.4zM479.8 102.6h3.4l.7 1.1-.7 1.1h-3.4l-.6-1.1zM479.8 105.1h3.4l.7 1.1-.7 1.1h-3.4l-.6-1.1z"/>
<path d="M480.5 103a.64 .64 0 0 1 .7 .6 .64 .64 0 0 1-.7 .6zM481.7 103.8h1M485.1 103.7h5.1M485.1 106.2h5.1M485.1 113.8h5.1M485.1 116.4h5.1M541 101.1h5.1M541 117.6h5.1M541 115.1h5.1M541 112.6h5.1M541 103.7h5.1M541 106.2h5.1"/>
<path d="M541 110h5.1M548.6 105.1h6.7v2.2h-6.7l-.6-1.1zM548.6 102.6h6.7v2.2h-6.7l-.6-1.1zM548.6 111.4h4.2v2.3h-4.2l-.6-1.1zM548.6 114h4.1v2.2h-4.1l-.6-1.1zM548.6 116.5h6.7v2.3h-6.7l-.6-1.2zM548.6 100h5.6v2.3h-5.6l-.6-1.2zM548.6 108.9h5.6v2.2h-5.6l-.6-1.1zM553.9 105.5h.8l-.5 1.3M553.9 117.3l.4-.4v1.3M553.9 118.2h.8M554.2 103.5l-.2-.4 .4-.1 .2 .4-.7 .4 .3 .4 .5-.2-.3-.5"/>
<path d="M582 110.2h2M35.1 134.3h5.5l.7 1.1-.7 1.1h-5.5zM54 127.2h2.5M56.5 120.8h12.7v12.7h-12.7zM61.6 138.6h2.5M62.9 138.6l1.2 2.5h-2.5zM62.9 136.1v7.6M79.4 127.2h2.5M81.9 120.8h12.7v12.7h-12.7zM87 138.6h2.5M88.3 138.6l1.2 2.5h-2.5zM88.3 136.1v7.6"/>
<path d="M104.8 127.2h2.5M107.3 120.8h12.7v12.7h-12.7zM112.4 138.6h2.5M113.7 138.6l1.2 2.5h-2.5zM113.7 136.1v7.6M130.2 127.2h2.5M132.7 120.8h12.7v12.7h-12.7zM137.8 138.6h2.5M139.1 138.6l1.2 2.5h-2.5zM139.1 136.1v7.6M155.6 127.2h2.5M158.1 120.8h12.7v12.7h-12.7z"/>
<path d="M163.2 138.6h2.5M164.5 138.6l1.2 2.5h-2.5zM164.5 136.1v7.6M181 127.2h2.5M183.5 120.8h12.7v12.7h-12.7zM188.6 138.6h2.5M189.9 138.6l1.2 2.5h-2.5zM189.9 136.1v7.6M206.4 127.2h2.5M208.9 120.8h12.7v12.7h-12.7zM214 138.6h2.5M215.3 138.6l1.2 2.5h-2.5z"/>
<path d="M215.3 136.1v7.6M231.8 127.2h2.5M234.3 120.8h12.7v12.7h-12.7zM239.4 138.6h2.5M240.7 138.6l1.2 2.5h-2.5zM240.7 136.1v7.6M257.2 127.2h2.5M259.7 120.8h12.7v12.7h-12.7zM264.8 138.6h2.5M266.1 138.6l1.2 2.5h-2.5zM266.1 136.1v7.6M282.6 127.2h2.5"/>
<path d="M285.1 120.8h12.7v12.7h-12.7zM290.2 138.6h2.5M291.5 138.6l1.2 2.5h-2.5zM291.5 136.1v7.6M308 127.2h2.5M310.5 120.8h12.7v12.7h-12.7zM315.6 138.6h2.5M316.9 138.6l1.2 2.5h-2.5zM316.9 136.1v7.6M333.4 127.2h2.5M335.9 120.8h12.7v12.7h-12.7zM341 138.6h2.5"/>
<path d="M342.3 138.6l1.2 2.5h-2.5zM342.3 136.1v7.6M477.1 131.8h6.1l.7 1.1-.7 1.1h-6.1zM477.1 129.2h6.1l.7 1.1-.7 1.2h-6.1zM477.9 138.1h5.3l.7 1.1-.7 1.2h-5.3zM478.4 121.6h4.8l.7 1.1-.7 1.1h-4.8zM478.4 124.1h4.8l.7 1.2-.7 1.1h-4.8zM485.1 139.2h5.1M485.1 122.7h5.1M485.1 125.3h5.1M485.1 130.3h5.1M485.1 132.9h5.1"/>
<path d="M541 139.2h5.1M541 136.7h5.1M541 134.2h5.1M541 131.6h5.1M541 129.1h5.1M541 126.5h5.1M541 124h5.1M541 121.5h5.1M548 138.1h9.2l.6 1.1-.6 1.2h-9.2zM548.6 128h5.6v2.2h-5.6l-.6-1.1zM548.6 120.3h8.5v2.3h-8.5l-.6-1.1zM548.6 122.9h8.3v2.2h-8.3l-.6-1.1z"/>
<path d="M548.6 135.6h6.1v2.2h-6.1l-.6-1.1zM548.6 133h5.6v2.3h-5.6l-.6-1.1zM548.6 125.4h6.7v2.3h-6.7l-.6-1.2zM548.6 130.5h6.7v2.2h-6.7l-.6-1.1zM553.4 136.1l.5-.1 .2 .3-.8 1h.8M554.5 125.8l-.5 .3-.1 .8 .3 .2 .4-.1 .1-.4-.3-.3-.5 .3M554.6 130.9h-.6l-.1 .6h.7v.5h-.7M555.8 121.4l.5-.1 .1-.4-.6-.2v1.3h.4l.3-.4-.3-.2M54 153.2h2.5M56.5 146.9h12.7v12.7h-12.7zM62.9 144.3v2.6M79.4 153.2h2.5"/>
<path d="M81.9 146.9h12.7v12.7h-12.7zM88.3 144.3v2.6M104.8 153.2h2.5M107.3 146.9h12.7v12.7h-12.7zM113.7 144.3v2.6M130.2 153.2h2.5M132.7 146.9h12.7v12.7h-12.7zM139.1 144.3v2.6M155.6 153.2h2.5M158.1 146.9h12.7v12.7h-12.7zM164.5 144.3v2.6M181 153.2h2.5"/>
<path d="M183.5 146.9h12.7v12.7h-12.7zM189.9 144.3v2.6M206.4 153.2h2.5M208.9 146.9h12.7v12.7h-12.7zM215.3 144.3v2.6M231.8 153.2h2.5M234.3 146.9h12.7v12.7h-12.7zM240.7 144.3v2.6M257.2 153.2h2.5M259.7 146.9h12.7v12.7h-12.7zM266.1 144.3v2.6M282.6 153.2h2.5"/>
<path d="M285.1 146.9h12.7v12.7h-12.7zM291.5 144.3v2.6M308 153.2h2.5M310.5 146.9h12.7v12.7h-12.7zM316.9 144.3v2.6M333.4 153.2h2.5M335.9 146.9h12.7v12.7h-12.7zM342.3 144.3v2.6M377 153.4h5.3l.6 1.1-.6 1.1h-5.3zM383.4 149.5h1.5v3.6h-1.5zM383.4 155.9h1.5v3.5h-1.5zM384.2 148.8v.7"/>
<path d="M384.2 153.1v.7M384.2 155.1v.8M384.2 159.4v.8M388.8 140.9h2.2v4.7l-1.1 .6-1.1-.6zM394.2 149.5h1.5v3.6h-1.5zM394.2 155.9h1.5v3.5h-1.5zM395 148.8v.7M395 153.1v.7M395 155.1v.8M395 159.4v.8M396.9 153.4h5v2.2h-5l-.7-1.1zM408.8 149.5h5.2l.7 1.2-.7 1.1h-5.2z"/>
<path d="M409 144.5h5l.7 1.1-.7 1.1h-5zM415.3 148.1v-1.2l-1.3 1.2 1.3 1.3v-1.3h5.1v1l.5 1.1M416.6 145.6h3.8v.5M419.1 143h10.2v10.2h-10.2zM419.1 158.9h10.2v10.2h-10.2zM420.4 150.2v.5h-3.8M420.9 146.1l-.5 1v1h-.5M423.5 146.3v3.6M423.8 145.4a2.74 2.74 0 0 1 2.7 2.8 2.74 2.74 0 0 1-2.7 2.7M423.8 146.3v3.6M424.1 146.3v3.6M424.3 150.5l-.6 .4 .7 .3"/>
<path d="M424.4 145.2l-.7 .3 .6 .3M427.6 148.1h.4M428 147.1v2M428.5 149.1v1.6h.8M429.3 145.6h-.8v1.5M433.7 149.5h6.4v2.3h-6.4l-.6-1.1zM433.7 144.5h6.4v2.2h-6.4l-.6-1.1zM476.6 141.9h6.6l.7 1.1-.7 1.2h-6.6zM485.1 143h5.1M541 153.2h5.1M541 148.1h5.1M541 145.6h5.1"/>
<path d="M541 150.7h5.1M541 158.3h5.1M541 155.7h5.1M541 143h5.1M548.6 141.9h4.9v2.3h-4.9l-.6-1.2zM548.6 157.2h6.1v2.2h-6.1l-.6-1.1zM548.6 149.5h4.9v2.3h-4.9l-.6-1.1zM548.6 154.6h4.9v2.3h-4.9l-.6-1.2zM548.6 144.5h9.6l.6 1.1-.6 1.1h-9.6zM548.6 147h4.9v2.2h-4.9l-.6-1.1zM548.6 152.1h4.9v2.2h-4.9l-.6-1.1zM548.6 159.7h4.9v2.2h-4.9l-.6-1.1z"/>
<path d="M553.5 157.7l.2-.1a.62 .62 0 0 1 .5 .6 .62 .62 0 0 1-.6 .6l-.2-.4zM10 160.2h2M35.1 160.3h5.5l.7 1.2-.7 1.1h-5.5zM41.2 178.1h6.4l.7 1.1-.7 1.2h-6.4zM53.3 169.2h6.4l.6 1.1-.6 1.2h-6.4zM54 179.2h2.5M56.5 172.9h12.7v12.7h-12.7zM61.6 164.6h2.5M62.9 164.6l1.2 2.6h-2.5zM62.9 162.1v7.6M62.9 170.3v2.6M79.4 179.2h2.5"/>
<path d="M81.9 172.9h12.7v12.7h-12.7zM87 164.6h2.5M88.3 164.6l1.2 2.6h-2.5zM88.3 162.1v7.6M88.3 170.3v2.6M104.8 179.2h2.5M107.3 172.9h12.7v12.7h-12.7zM112.4 164.6h2.5M113.7 164.6l1.2 2.6h-2.5zM113.7 162.1v7.6M113.7 170.3v2.6M130.2 179.2h2.5"/>
<path d="M132.7 172.9h12.7v12.7h-12.7zM137.8 164.6h2.5M139.1 164.6l1.2 2.6h-2.5zM139.1 162.1v7.6M139.1 170.3v2.6M155.6 179.2h2.5M158.1 172.9h12.7v12.7h-12.7zM163.2 164.6h2.5M164.5 164.6l1.2 2.6h-2.5zM164.5 162.1v7.6M164.5 170.3v2.6M181 179.2h2.5"/>
<path d="M183.5 172.9h12.7v12.7h-12.7zM188.6 164.6h2.5M189.9 164.6l1.2 2.6h-2.5zM189.9 162.1v7.6M189.9 170.3v2.6M206.4 179.2h2.5M208.9 172.9h12.7v12.7h-12.7zM214 164.6h2.5M215.3 164.6l1.2 2.6h-2.5zM215.3 162.1v7.6M215.3 170.3v2.6M231.8 179.2h2.5"/>
<path d="M234.3 172.9h12.7v12.7h-12.7zM239.4 164.6h2.5M240.7 164.6l1.2 2.6h-2.5zM240.7 162.1v7.6M240.7 170.3v2.6M257.2 179.2h2.5M259.7 172.9h12.7v12.7h-12.7zM264.8 164.6h2.5M266.1 164.6l1.2 2.6h-2.5zM266.1 162.1v7.6M266.1 170.3v2.6M282.6 179.2h2.5"/>
<path d="M285.1 172.9h12.7v12.7h-12.7zM290.2 164.6h2.5M291.5 164.6l1.2 2.6h-2.5zM291.5 162.1v7.6M291.5 170.3v2.6M308 179.2h2.5M310.5 172.9h12.7v12.7h-12.7zM315.6 164.6h2.5M316.9 164.6l1.2 2.6h-2.5zM316.9 162.1v7.6M316.9 170.3v2.6M333.4 179.2h2.5"/>
<path d="M335.9 172.9h12.7v12.7h-12.7zM341 164.6h2.5M342.3 164.6l1.2 2.6h-2.5zM342.3 162.1v7.6M342.3 170.3v2.6M345.4 168.6h6.4v2.2h-6.4l-.6-1.1zM374.4 160.3h8.5v2.3h-8.5l-.6-1.1zM384.2 167.8v1.3h1.2l-1.2 1.2-1.3-1.2h1.3M384.2 162.1v2M384.2 165.1v2.1M395 167.8v1.3h1.2l-1.2 1.2-1.3-1.2h1.3M395 162.1v2"/>
<path d="M395 165.1v2.1M396.2 160.3h8.3l.6 1.2-.6 1.1h-8.3zM408.8 165.4h5.2l.7 1.1-.7 1.2h-5.2zM409 160.3h5l.7 1.2-.7 1.1h-5zM415.3 164v-1.3l-1.3 1.3 1.3 1.3v-1.3h5.1v1l.5 1M416.6 161.5h3.8v.5M420.4 166v.5h-3.8M420.9 162l-.5 1v1h-.5M423.5 162.2v3.6M423.8 161.3a2.74 2.74 0 0 1 2.7 2.8 2.74 2.74 0 0 1-2.7 2.7M423.8 162.2v3.6M424.1 162.2v3.6"/>
<path d="M424.3 166.4l-.6 .4 .7 .2M424.4 161.1l-.7 .2 .6 .4M427.6 164h.4M428 163v2M428.5 165v1.5h.8M429.3 161.5h-.8v1.5M433.7 165.4h6.4v2.3h-6.4l-.6-1.2zM433.7 160.3h6.4v2.3h-6.4l-.6-1.1zM438.8 162h.7M504.2 172.3v1.2h1.3l-1.3 1.3-1.3-1.3h1.3M504.2 165.9v5.1M511.8 172.3v1.2h1.3l-1.3 1.3-1.3-1.3h1.3"/>
<path d="M511.8 165.9v5.1M519.4 172.3v1.2h1.3l-1.3 1.3-1.2-1.3h1.2M519.4 165.9v5.1M527 172.3v1.2h1.3l-1.3 1.3-1.2-1.3h1.2M527 165.9v5.1M541 160.8h5.1M541 163.4h5.1M548.6 162.2h4.9v2.3h-4.9l-.6-1.1zM552.2 163.9h.7M582 160.2h2M155.6 198.3h2.5M158.1 191.9h12.7v12.7h-12.7z"/>
<path d="M164.5 189.4v2.5M181 198.3h2.5M183.5 191.9h12.7v12.7h-12.7zM189.9 189.4v2.5M206.4 198.3h2.5M208.9 191.9h12.7v12.7h-12.7zM215.3 189.4v2.5M328.4 181.1l1.2-.6 1.1 .6v6.4h-2.3zM398.8 195.1v-1.3l-1.3 1.3 1.3 1.3v-1.3h1.2M401.3 195.1h2.6M404.1 194.8a3.2 3.2 0 0 1 3.5-.7 3.2 3.2 0 0 1 2 2.9v1.9a3.2 3.2 0 0 1-3.2 3.2 3.2 3.2 0 0 1-3.2-3.2v-1.9a3 3 0 0 1 .9-2.2zM406.4 197.7v1.9l.5 .1-1 .2 1 .3-1 .2 1 .3-1 .3 .5 .1v2.9"/>
<path d="M406.7 197.7l-2.6-2.6v3.8h.4l.1 .5 .3-1 .2 1 .3-1 .2 1 .3-1 .1 .5h.4M411.5 195.1h-2.8l-2.6 2.6M422.9 186.2h1.3l-1.3-1.2-1.3 1.2h1.3v1.3M422.9 188.8v2M422.9 191.8v2M431.2 194h5.3l.7 1.1-.7 1.1h-5.3l-.7-1.1zM468.1 185.2h2.3v6.1l-1.1 .6-1.2-.6zM469.3 195.7v2.1M469.3 198.8v2M475.6 195.5v1.3h5.1v-1.3M475.6 190.9v-1.2h5.1v1.2M475.6 193.2h.5"/>
<path d="M478.2 184.3h1.2l-1.2-1.3-1.3 1.3h1.3v1.3M480.2 193.2h.5M485.9 185.2h2.3v6.1l-1.2 .6-1.1-.6zM487 195.7v2.1M487 198.8v2M10 210.2h2M389 209.2h4.7l.6 1.2-.6 1.1h-4.7zM394.3 210.4h2.6M396.9 209.1h5.1M399.4 207.3v1.8M402 210.4h2.5M408.3 210.4h7.6"/>
<path d="M410.8 209.1l2.6 1.3-2.6 1.2zM413.4 209.1v2.5M418.3 213.7h1.6v3.5h-1.6zM419.1 219.2v1.3h1.3l-1.3 1.3-1.3-1.3h1.3M419.1 212.9v.8M419.1 217.2v.8M422.9 219.2v1.3h1.3l-1.3 1.3-1.3-1.3h1.3M422.9 212.9v2M422.9 215.9v2.1M431.2 209.2h6.6l.7 1.2-.7 1.1h-6.6l-.7-1.1zM478.2 202.1v1.3h1.2l-1.2 1.2-1.3-1.2h1.3M582 210.2h2"/>
<path d="M334.2 238.9h4.3M340.4 238.9h1.2v-1.2l1.3 1.2-1.3 1.3v-1.3M417.8 238.3h7.6M420.4 238.3l2.5-1.3v2.6zM420.4 237v2.6M67.5 253.2h2.2v2.9l-1.1 .6-1.1-.6zM73 259.2v.8M80 259.2v.8M87 259.2v.8M94 259.2v.8M101 259.2v.8M107.9 259.2v.8"/>
<path d="M114.9 259.2v.8M121.9 259.2v.8M128.9 259.2v.8M135.9 259.2v.8M142.9 259.2v.8M149.9 259.2v.8M208.9 243.4h20.3v63.5h-20.3zM228.2 258.4h1v.5h-1zM228.2 245.7h1v.5h-1zM228.2 248.2h1v.5h-1zM229.2 245.9h5.1M229.2 258.6h5.1"/>
<path d="M229.2 248.5h5.1M236.9 258.6h.7M237.6 257.9h3.6v1.5h-3.6zM241.2 258.6h.7M243.2 258.6h1.3v-1.3l1.2 1.3-1.2 1.3v-1.3M245.7 244.8h5.5l.7 1.1-.7 1.1h-5.5zM284.1 249.7h4.2M284.1 247.2h4.2M284.1 244.6h4.2M284.1 242.1h4.2M290.2 249.7h1.3v-1.2l1.2 1.2-1.2 1.3v-1.3M290.8 241h2.9v2.2h-2.9l-.6-1.1z"/>
<path d="M290.8 246.1h4.1v2.2h-4.1l-.6-1.1zM290.8 243.5h4.2v2.3h-4.2l-.6-1.2zM334.2 251.6h4.3M334.2 249.1h4.3M334.2 246.5h4.3M334.2 244h4.3M334.2 241.5h4.3M341 248h6.8v2.2h-6.8l-.6-1.1zM341 245.4h6.4v2.3h-6.4l-.6-1.2zM341 250.5h4.7v2.2h-4.7l-.6-1.1zM341 242.9h6.7v2.2h-6.7l-.6-1.1zM341 240.4h5.4v2.2h-5.4l-.6-1.1z"/>
<path d="M390.8 249.2h5.4l.7 1.2-.7 1.1h-5.4zM398.1 250.4h5.1M399.4 249.9h2.6v1h-2.6zM402 249.3h-.6l-1.5 2.1h-.5M405.9 245.6l1.1-.7 1.2 .7v2.9h-2.3zM407 258v1.2h1.3l-1.3 1.3-1.2-1.3h1.2M407 253.4l1.1 1.5h-2.1zM407 251.6v5.1M407.8 253.2h.3v.2h-2.1v.3h.3M412.7 256.7v2M412.7 259.8v2M414 250.4h2.6"/>
<path d="M416.6 248.5h10.1v6.9h-10.1zM421.6 255.4v2.6M426.7 250.4h2.6M430.5 257.3v2.1M438.1 249.2h4.7l.7 1.2-.7 1.1h-4.7zM10 260.2h2M71.8 269.4h2.5M72.3 277.2h1.5v3.5h-1.5zM72.3 260h1.5v3.6h-1.5zM73 263.6v3.3h1.3h-2.5l1.2 2.5 1.3-2.5h-1.3M73 269.4v2.5M73 276.4v.8"/>
<path d="M78.7 269.4h2.6M79.2 277.2h1.6v3.5h-1.6zM79.2 260h1.6v3.6h-1.6zM80 263.6v3.3h1.3h-2.6l1.3 2.5 1.3-2.5h-1.3M80 269.4v2.5M80 276.4v.8M85.7 269.4h2.6M86.2 260h1.6v3.6h-1.6zM86.2 277.2h1.6v3.5h-1.6zM87 263.6v3.3h1.3h-2.6l1.3 2.5 1.3-2.5h-1.3M87 269.4v2.5M87 276.4v.8"/>
<path d="M92.7 269.4h2.5M93.2 277.2h1.5v3.5h-1.5zM93.2 260h1.5v3.6h-1.5zM94 263.6v3.3h1.2h-2.5l1.3 2.5 1.2-2.5h-1.2M94 269.4v2.5M94 276.4v.8M99.7 269.4h2.5M100.2 277.2h1.5v3.5h-1.5zM100.2 260h1.5v3.6h-1.5zM101 263.6v3.3h1.2h-2.5l1.3 2.5 1.2-2.5h-1.2M101 269.4v2.5M101 276.4v.8"/>
<path d="M106.7 269.4h2.5M107.2 277.2h1.5v3.5h-1.5zM107.2 260h1.5v3.6h-1.5zM107.9 263.6v3.3h1.3h-2.5l1.2 2.5 1.3-2.5h-1.3M107.9 269.4v2.5M107.9 276.4v.8M113.7 269.4h2.5M114.2 277.2h1.5v3.5h-1.5zM114.2 260h1.5v3.6h-1.5zM114.9 263.6v3.3h1.3h-2.5l1.2 2.5 1.3-2.5h-1.3M114.9 269.4v2.5M114.9 276.4v.8"/>
<path d="M120.6 269.4h2.6M121.2 277.2h1.5v3.5h-1.5zM121.2 260h1.5v3.6h-1.5zM121.9 263.6v3.3h1.3h-2.6l1.3 2.5 1.3-2.5h-1.3M121.9 269.4v2.5M121.9 276.4v.8M127.6 269.4h2.6M128.1 277.2h1.6v3.5h-1.6zM128.1 260h1.6v3.6h-1.6zM128.9 263.6v3.3h1.3h-2.6l1.3 2.5 1.3-2.5h-1.3M128.9 269.4v2.5M128.9 276.4v.8"/>
<path d="M134.6 269.4h2.6M135.1 277.2h1.6v3.5h-1.6zM135.1 260h1.6v3.6h-1.6zM135.9 263.6v3.3h1.3h-2.6l1.3 2.5 1.3-2.5h-1.3M135.9 269.4v2.5M135.9 276.4v.8M141.6 269.4h2.5M142.1 277.2h1.5v3.5h-1.5zM142.1 260h1.5v3.6h-1.5zM142.9 263.6v3.3h1.2h-2.5l1.3 2.5 1.2-2.5h-1.2M142.9 269.4v2.5M142.9 276.4v.8"/>
<path d="M148.6 269.4h2.5M149.1 277.2h1.5v3.5h-1.5zM149.1 260h1.5v3.6h-1.5zM149.9 263.6v3.3h1.2h-2.5l1.3 2.5 1.2-2.5h-1.2M149.9 269.4v2.5M149.9 276.4v.8M212.7 277.7l.2 .4 .4 .2 .5-.2 .2-.4M212.7 270l.2-.4 .4-.2 .5 .2 .2 .4M228.2 277.4h1v.5h-1zM228.2 274.9h1v.5h-1zM228.2 263.4h1v.5h-1zM229.2 263.7h5.1"/>
<path d="M229.2 275.1h5.1M229.2 277.7h5.1M236.9 263.7h.7M237.6 262.9h3.6v1.6h-3.6zM239.4 274h6.9l.6 1.1-.6 1.1h-6.9l-.6-1.1zM241.2 263.7h.7M243.2 263.7h1.3v-1.3l1.2 1.3-1.2 1.3v-1.3M245.6 274.9l-.5 .1 .5 .3v.3h-.5M284.1 278.3h4.2M284.1 275.8h4.2M284.1 273.2h4.2M284.1 270.7h4.2"/>
<path d="M290.8 277.2h6.7v2.2h-6.7l-.6-1.1zM290.8 269.6h6.7v2.2h-6.7l-.6-1.1zM290.8 272.1h6.7v2.2h-6.7l-.6-1.1zM290.8 274.6h6.7v2.3h-6.7l-.6-1.1zM296.1 275h.7l-.4 .5 .4 .2v.5h-.7M296.1 270.3l.4-.3v1.2M296.1 272.6l.5-.1 .2 .4-.7 .9h.7M296.1 271.2h.7M296.4 277.5l-.3 .9h.8M296.7 278v.9M334.2 278.3h4.3M334.2 275.8h4.3"/>
<path d="M334.2 273.2h4.3M334.2 270.7h4.3M341 277.2h6.6v2.2h-6.6l-.6-1.1zM341 274.6h6.6v2.3h-6.6l-.6-1.1zM341 269.6h6.6v2.2h-6.6l-.6-1.1zM341 272.1h6.6v2.2h-6.6l-.6-1.1zM346.2 275h.9l-.6 1.3M346.5 278.1l-.1-.4 .4-.1 .2 .4-.7 .4 .2 .5 .5-.3-.2-.5M346.9 272.5l-.5 .3-.1 .7 .2 .3 .5-.1v-.5l-.2-.2-.5 .2M347 270h-.6l-.1 .6h.7v.5h-.7M421.6 267.5v1.3h1.3l-1.3 1.2-1.2-1.2h1.2M430.5 260.4v2"/>
<path d="M582 260.2h2M71.8 287.8h2.5M72.3 294.9h1.5v3.6h-1.5zM73 282.7v2.6h1.3h-2.5l1.2 2.5 1.3-2.5h-1.3M73 280.7v.8M73 287.8v2.6M73 294.2v.7M73 298.5v.8M78.7 287.8h2.6M79.2 294.9h1.6v3.6h-1.6zM80 282.7v2.6h1.3h-2.6l1.3 2.5 1.3-2.5h-1.3M80 280.7v.8"/>
<path d="M80 287.8v2.6M80 294.2v.7M80 298.5v.8M85.7 287.8h2.6M86.2 294.9h1.6v3.6h-1.6zM87 282.7v2.6h1.3h-2.6l1.3 2.5 1.3-2.5h-1.3M87 280.7v.8M87 287.8v2.6M87 294.2v.7M87 298.5v.8M92.7 287.8h2.5M93.2 294.9h1.5v3.6h-1.5z"/>
<path d="M94 282.7v2.6h1.2h-2.5l1.3 2.5 1.2-2.5h-1.2M94 280.7v.8M94 287.8v2.6M94 294.2v.7M94 298.5v.8M99.7 287.8h2.5M100.2 294.9h1.5v3.6h-1.5zM101 282.7v2.6h1.2h-2.5l1.3 2.5 1.2-2.5h-1.2M101 280.7v.8M101 287.8v2.6M101 294.2v.7M101 298.5v.8"/>
<path d="M106.7 287.8h2.5M107.2 294.9h1.5v3.6h-1.5zM107.9 282.7v2.6h1.3h-2.5l1.2 2.5 1.3-2.5h-1.3M107.9 280.7v.8M107.9 287.8v2.6M107.9 294.2v.7M107.9 298.5v.8M113.7 287.8h2.5M114.2 294.9h1.5v3.6h-1.5zM114.9 282.7v2.6h1.3h-2.5l1.2 2.5 1.3-2.5h-1.3M114.9 280.7v.8M114.9 287.8v2.6"/>
<path d="M114.9 294.2v.7M114.9 298.5v.8M120.6 287.8h2.6M121.2 294.9h1.5v3.6h-1.5zM121.9 282.7v2.6h1.3h-2.6l1.3 2.5 1.3-2.5h-1.3M121.9 280.7v.8M121.9 287.8v2.6M121.9 294.2v.7M121.9 298.5v.8M127.6 287.8h2.6M128.1 294.9h1.6v3.6h-1.6zM128.9 282.7v2.6h1.3h-2.6l1.3 2.5 1.3-2.5h-1.3"/>
<path d="M128.9 280.7v.8M128.9 287.8v2.6M128.9 294.2v.7M128.9 298.5v.8M134.6 287.8h2.6M135.1 294.9h1.6v3.6h-1.6zM135.9 282.7v2.6h1.3h-2.6l1.3 2.5 1.3-2.5h-1.3M135.9 280.7v.8M135.9 287.8v2.6M135.9 294.2v.7M135.9 298.5v.8M141.6 287.8h2.5"/>
<path d="M142.1 294.9h1.5v3.6h-1.5zM142.9 282.7v2.6h1.2h-2.5l1.3 2.5 1.2-2.5h-1.2M142.9 280.7v.8M142.9 287.8v2.6M142.9 294.2v.7M142.9 298.5v.8M148.6 287.8h2.5M149.1 294.9h1.5v3.6h-1.5zM149.9 282.7v2.6h1.2h-2.5l1.3 2.5 1.2-2.5h-1.2M149.9 280.7v.8M149.9 287.8v2.6M149.9 294.2v.7"/>
<path d="M149.9 298.5v.8M228.2 285h1v.5h-1zM228.2 282.5h1v.5h-1zM229.2 282.7h5.1M229.2 285.3h5.1M239.4 281.6h6.9l.6 1.1-.6 1.2h-6.9l-.6-1.2zM240.7 285.3h.7M241.4 284.5h3.6v1.5h-3.6zM245 285.3h.7M245.6 282.5l-.5 .1 .5 .3v.4h-.5M247.6 284.2h5.5l.7 1.1-.7 1.1h-5.5zM292.3 296.4h2.2v2.9l-1.1 .6-1.1-.6z"/>
<path d="M10 310.2h2M71.8 305.6h2.5M72.3 312.1h1.5v3.5h-1.5zM73 317.7v2.5h1.3h-2.5l1.2 2.5 1.3-2.5h-1.3M73 300.5v2.6h1.3h-2.5l1.2 2.5 1.3-2.5h-1.3M73 305.6v2.5M73 311.3v.8M73 315.6v.8M78.7 305.6h2.6M79.2 312.1h1.6v3.5h-1.6zM80 317.7v2.5h1.3h-2.6l1.3 2.5 1.3-2.5h-1.3M80 300.5v2.6h1.3h-2.6l1.3 2.5 1.3-2.5h-1.3"/>
<path d="M80 305.6v2.5M80 311.3v.8M80 315.6v.8M85.7 305.6h2.6M86.2 312.1h1.6v3.5h-1.6zM87 317.7v2.5h1.3h-2.6l1.3 2.5 1.3-2.5h-1.3M87 300.5v2.6h1.3h-2.6l1.3 2.5 1.3-2.5h-1.3M87 305.6v2.5M87 311.3v.8M87 315.6v.8M92.7 305.6h2.5M93.2 312.1h1.5v3.5h-1.5z"/>
<path d="M94 317.7v2.5h1.2h-2.5l1.3 2.5 1.2-2.5h-1.2M94 300.5v2.6h1.2h-2.5l1.3 2.5 1.2-2.5h-1.2M94 305.6v2.5M94 311.3v.8M94 315.6v.8M99.7 305.6h2.5M100.2 312.1h1.5v3.5h-1.5zM101 317.7v2.5h1.2h-2.5l1.3 2.5 1.2-2.5h-1.2M101 300.5v2.6h1.2h-2.5l1.3 2.5 1.2-2.5h-1.2M101 305.6v2.5M101 311.3v.8M101 315.6v.8"/>
<path d="M103.5 317.7v2.5h1.3h-2.6l1.3 2.5 1.3-2.5h-1.3M106.7 305.6h2.5M107.2 312.1h1.5v3.5h-1.5zM107.9 317.7v2.5h1.3h-2.5l1.2 2.5 1.3-2.5h-1.3M107.9 300.5v2.6h1.3h-2.5l1.2 2.5 1.3-2.5h-1.3M107.9 305.6v2.5M107.9 311.3v.8M107.9 315.6v.8M110.5 317.7v2.5h1.3h-2.6l1.3 2.5 1.3-2.5h-1.3M113.7 305.6h2.5M114.2 312.1h1.5v3.5h-1.5zM114.9 317.7v2.5h1.3h-2.5l1.2 2.5 1.3-2.5h-1.3"/>
<path d="M114.9 300.5v2.6h1.3h-2.5l1.2 2.5 1.3-2.5h-1.3M114.9 305.6v2.5M114.9 311.3v.8M114.9 315.6v.8M117.5 317.7v2.5h1.2h-2.5l1.3 2.5 1.2-2.5h-1.2M120.6 305.6h2.6M121.2 312.1h1.5v3.5h-1.5zM121.9 317.7v2.5h1.3h-2.6l1.3 2.5 1.3-2.5h-1.3M121.9 300.5v2.6h1.3h-2.6l1.3 2.5 1.3-2.5h-1.3M121.9 305.6v2.5M121.9 311.3v.8M121.9 315.6v.8"/>
<path d="M127.6 305.6h2.6M128.1 312.1h1.6v3.5h-1.6zM128.9 317.7v2.5h1.3h-2.6l1.3 2.5 1.3-2.5h-1.3M128.9 300.5v2.6h1.3h-2.6l1.3 2.5 1.3-2.5h-1.3M128.9 305.6v2.5M128.9 311.3v.8M128.9 315.6v.8M134.6 305.6h2.6M135.1 312.1h1.6v3.5h-1.6zM135.9 317.7v2.5h1.3h-2.6l1.3 2.5 1.3-2.5h-1.3M135.9 300.5v2.6h1.3h-2.6l1.3 2.5 1.3-2.5h-1.3M135.9 305.6v2.5"/>
<path d="M135.9 311.3v.8M135.9 315.6v.8M141.6 305.6h2.5M142.1 312.1h1.5v3.5h-1.5zM142.9 317.7v2.5h1.2h-2.5l1.3 2.5 1.2-2.5h-1.2M142.9 300.5v2.6h1.2h-2.5l1.3 2.5 1.2-2.5h-1.2M142.9 305.6v2.5M142.9 311.3v.8M142.9 315.6v.8M148.6 305.6h2.5M149.1 312.1h1.5v3.5h-1.5zM149.9 317.7v2.5h1.2h-2.5l1.3 2.5 1.2-2.5h-1.2"/>
<path d="M149.9 300.5v2.6h1.2h-2.5l1.3 2.5 1.2-2.5h-1.2M149.9 305.6v2.5M149.9 311.3v.8M149.9 315.6v.8M205.4 314.5h2v5.1h-2zM206.4 313.2v1.3M206.4 319.6v1.2M211.5 306.9v5.1M211.5 314.5v2M211.5 317.5v2.1M216.3 305.9h.5v1h-.5zM216.5 306.9v5.1"/>
<path d="M218.8 305.9h.5v1h-.5zM219.1 314.5v1.3h1.2l-1.2 1.2-1.3-1.2h1.3M219.1 306.9v5.1M228.2 304.1h1v.5h-1zM228.2 301.5h1v.5h-1zM229.2 301.8h5.1M229.2 304.3h5.1M274.3 309.6h9.5l.7 1.1-.7 1.1h-9.5zM285.7 310.7h2.6M288.3 305.6h10.1v10.2h-10.1zM293.4 303.1v2.5M293.4 315.8v2.5"/>
<path d="M294.6 313.2h.5M295.7 313.2l-1.1 1v-.5M295.7 312.2l-1.1 1v-.5M296 312.2h2.1l-1 2zM296 314.2h2.1M297.1 311.7v3M298.4 310.7h2.6M302.3 310.7h2.5M304.8 305.6h10.2v10.2h-10.2zM309.9 303.1v2.5M309.9 315.8v2.5M311.1 313.2h.6"/>
<path d="M312.2 313.2l-1.1 1v-.5M312.2 312.2l-1.1 1v-.5M312.5 312.2h2.1l-1 2zM312.5 314.2h2.1M313.6 311.7v3M315 310.7h2.5M318.8 310.7h2.5M321.3 305.6h10.2v10.2h-10.2zM326.4 303.1v2.5M326.4 315.8v2.5M327.7 313.2h.5M328.7 313.2l-1 1v-.5"/>
<path d="M328.7 312.2l-1 1v-.5M329.1 312.2h2l-1 2zM329.1 314.2h2M330.1 311.7v3M331.5 310.7h2.5M335.3 310.7h2.5M337.8 305.6h10.2v10.2h-10.2zM342.9 303.1v2.5M342.9 315.8v2.5M344.2 313.2h.5M345.2 313.2l-1 1v-.5M345.2 312.2l-1 1v-.5"/>
<path d="M345.6 312.2h2l-1 2zM345.6 314.2h2M346.6 311.7v3M348 310.7h2.5M391.3 305.8h6.8l.7 1.1-.7 1.1h-6.8l-.7-1.1zM391.9 306.2a.64 .64 0 0 1 .7 .6 .64 .64 0 0 1-.7 .6zM396.2 313.9h15.3v15.2h-15.3zM397.5 318.9h12.7v5.1h-12.7zM399 317.9l2.1 1-2.1 1.1zM401.1 317.9v2.1M401.3 308.8v7.6h2.6M406.4 308.8v7.6h-2.5v2.5"/>
<path d="M406.7 317.9l2 1-2 1.1zM407.7 306.9h.7M408.4 306.1h3.6v1.5h-3.6zM408.7 317.9v2.1M412 306.9h.7M414.7 305.8h3.4l.6 1.1-.6 1.1h-3.4l-.7-1.1zM415.2 306.2a.64 .64 0 0 1 .7 .6 .64 .64 0 0 1-.7 .6zM416.4 307h1M458.1 308.1h2v5.1h-2zM459.1 315.8v1.2h1.3l-1.3 1.3-1.3-1.3h1.3M459.1 306.9v1.2M459.1 313.2v1.3"/>
<path d="M464.2 308.1v2.1M464.2 311.2v2M466.7 306.9h7.6M469.3 306.9l2.5-1.3v2.5zM469.3 305.6v2.5M475.6 305.8h5.3v2.2h-5.3l-.6-1.1zM582 310.2h2M46.7 329.3h9.2l.6 1.1-.6 1.1h-9.2zM58.4 330.4h.8M59.2 329.6h3.5v1.5h-3.5zM62.7 330.4h.8M64 333h1.5v3.6h-1.5z"/>
<path d="M64.8 332.3v.7M64.8 336.6v.8M65.4 330.4h5.3M70.7 328.5v3.8M71.2 330.4h1.8v5M71.2 328.1v1M71.2 329.9v1M71.2 331.6v1.1M71.2 328.6h1.8M71.8 322.7h2.5M73 328.6h.8v3.5h-2.6M73 322.7v5.9"/>
<path d="M73.3 329.9l1 .2M73.8 330l.4 .6h-.8zM78.7 322.7h2.6M80 322.7v2.6M85.7 322.7h2.6M87 322.7v2.6M92.7 322.7h2.5M94 322.7v2.6M99.7 322.7h5.1M101 322.7v2.6M103.5 322.7v2.6M106.7 322.7h5.1"/>
<path d="M107.9 322.7v2.6M110.5 322.7v2.6M113.7 322.7h5M114.9 322.7v2.6M117.5 322.7v2.6M120.6 322.7h2.6M121.9 322.7v2.6M127.6 322.7h2.6M128.9 322.7v2.6M134.6 322.7h2.6M135.9 322.7v2.6M141.6 322.7h2.5"/>
<path d="M142.9 322.7v2.6M148.6 322.7h2.5M149.9 322.7v2.6M206.4 322.1v1.3h1.2l-1.2 1.3-1.3-1.3h1.3M274.3 333.1h9.5l.7 1.1-.7 1.1h-9.5zM285.7 334.2h2.6M288.3 329.1h10.1v10.2h-10.1zM292.3 320.5h2.2v2.9l-1.1 .6-1.1-.6zM293.4 326.6v2.5M293.4 339.3v2.5M294.6 336.7h.5M295.7 336.7l-1.1 1v-.5"/>
<path d="M295.7 335.7l-1.1 1v-.5M296 335.7h2.1l-1 2zM296 337.7h2.1M297.1 335.2v3M298.4 334.2h2.6M302.3 334.2h2.5M304.8 329.1h10.2v10.2h-10.2zM309.9 320.8v1.3h1.2l-1.2 1.3-1.3-1.3h1.3M309.9 326.6v2.5M309.9 339.3v2.5M311.1 336.7h.6M312.2 336.7l-1.1 1v-.5"/>
<path d="M312.2 335.7l-1.1 1v-.5M312.5 335.7h2.1l-1 2zM312.5 337.7h2.1M313.6 335.2v3M315 334.2h2.5M318.8 334.2h2.5M321.3 329.1h10.2v10.2h-10.2zM326.4 326.6v2.5M326.4 339.3v2.5M327.7 336.7h.5M328.7 336.7l-1 1v-.5M328.7 335.7l-1 1v-.5"/>
<path d="M329.1 335.7h2l-1 2zM329.1 337.7h2M330.1 335.2v3M331.5 334.2h2.5M335.3 334.2h2.5M337.8 329.1h10.2v10.2h-10.2zM342.9 326.6v2.5M342.9 339.3v2.5M344.2 336.7h.5M345.2 336.7l-1 1v-.5M345.2 335.7l-1 1v-.5M345.6 335.7h2l-1 2z"/>
<path d="M345.6 337.7h2M346.6 335.2v3M348 334.2h2.5M387.3 321.5v-1.3l-1.2 1.3 1.2 1.2v-1.2h1.3M391.2 321.5h25.4M391.3 334.3h6.8l.7 1.1-.7 1.2h-6.8l-.7-1.2zM399 323l2.1 1-2.1 1zM401.1 323v2M402.8 320.5l2.1 1-2.1 1zM403.9 324v2.6h2.5v7.6M403.9 326.6h-2.6v7.6M404.4 320.5h.5v2"/>
<path d="M406.7 323l2 1-2 1zM407.7 335.4h.7M408.4 334.7h3.6v1.5h-3.6zM408.7 323v2M412 335.4h.7M414.7 334.3h3.4l.6 1.1-.6 1.2h-3.4l-.7-1.2zM417.8 329.1v1.3h1.3l-1.3 1.2-1.2-1.2h1.2M417.8 322.7v2.1M417.8 325.8v2M421 320.4h5.5v2.2h-5.5l-.6-1.1zM73 342.4v1.3h1.3l-1.3 1.3-1.2-1.3h1.2M309.9 344.3v1.3h1.2l-1.2 1.3-1.3-1.3h1.3"/>
<path d="M10 360.2h2M474 376.2h108v32h-108zM582 360.2h2M474 397.7h108M474 391.7h108M484.6 392.2l-1.3 2M490 395.6l-.4-.1-.3 .3v.6h.7M490.6 395.6h.6l.1 .9M490.6 395v1.5M500.7 383.9l-.4-.1-.3 .3v.6l.7 .1M500.7 383.3v1.5M501.4 383.8v1"/>
<path d="M501.8 383.8l-.4 .3M502.3 383.3v.2M502.3 383.8v1M503 384l.6-.1 .1 .9M503 383.8v1M503.7 384l.2-.2 .4 .1v.9M516.6 386.9l-.4-.1-.3 .3 .1 .6h.6M516.6 386.3v1.5M518.2 386.5a.66 .66 0 0 0-1 .6 .66 .66 0 0 0 1 .6M518.8 386.9h.6l.1 .9M519.5 387.2l-.8 .3 .2 .3 .6-.1M520.2 386.9l.4-.1 .3 .3-.1 .6h-.6"/>
<path d="M520.2 386.3v1.5M521.5 386.3v1.3l.2 .2M522.2 387.3l.8-.1-.1-.3-.4-.1-.3 .2 .1 .7h.6M524.1 386.9l-.4-.1-.2 .2 .1 .3 .5 .1v.3h-.6M60 408.2v2M110 408.2v2M160 408.2v2M210 408.2v2M260 408.2v2M310 408.2v2M360 408.2v2M410 408.2v2"/>
<path d="M460 408.2v2M474 404.7h108M474 401.7h108M483.1 402.6l.6-.2 .3 .5-.9 1h.9M494 401.7v3M499.3 405.2h-.7v.7h.7v.7h-.7M500 406.6v.1M500.7 405.7l.4-.5v1.5M500.7 406.7h.8M502.2 406.6v.1M503.2 405.1l-.4 1.1h1M503.6 405.7v1"/>
<path d="M510 408.2v2M514 403.1l-.2 .3-.5-.1v-.7l.5-.2 .2 .3-.2 1.1-.5 .1M514.7 403.4h1.1M516.5 402.9l.4-.5v1.5M516.5 403.9h.8M518.1 402.5l.2-.1a.8 .8 0 0 1 .5 .8 .8 .8 0 0 1-.5 .7 1 1 0 0 1-.2-1.4zM536.5 409.7h.8M558 401.7v6.5M560 408.2v2M566.8 405.1l-1.2 2M567.3 405.7l.4-.5v1.5M567.3 406.7h.8"/>
<circle cx="423.8" cy="148.1" r="1.91"/>
<circle cx="428.5" cy="149.1" r=".13"/>
<circle cx="428.5" cy="147.1" r=".13"/>
<circle cx="423.8" cy="164" r="1.91"/>
<circle cx="428.5" cy="165" r=".13"/>
<circle cx="428.5" cy="163" r=".13"/>
<circle cx="404.1" cy="195.1" r=".13"/>
<circle cx="406.4" cy="198.9" r=".13"/>
<circle cx="397.4" cy="210.4" r=".51"/>
<circle cx="401.4" cy="210.4" r=".51"/>
<circle cx="73" cy="268.1" r="2.84"/>
<circle cx="80" cy="268.1" r="2.84"/>
<circle cx="87" cy="268.1" r="2.84"/>
<circle cx="94" cy="268.1" r="2.84"/>
<circle cx="101" cy="268.1" r="2.84"/>
<circle cx="107.9" cy="268.1" r="2.84"/>
<circle cx="114.9" cy="268.1" r="2.84"/>
<circle cx="121.9" cy="268.1" r="2.84"/>
<circle cx="128.9" cy="268.1" r="2.84"/>
<circle cx="135.9" cy="268.1" r="2.84"/>
<circle cx="142.9" cy="268.1" r="2.84"/>
<circle cx="149.9" cy="268.1" r="2.84"/>
<circle cx="73" cy="286.6" r="2.84"/>
<circle cx="80" cy="286.6" r="2.84"/>
<circle cx="87" cy="286.6" r="2.84"/>
<circle cx="94" cy="286.6" r="2.84"/>
<circle cx="101" cy="286.6" r="2.84"/>
<circle cx="107.9" cy="286.6" r="2.84"/>
<circle cx="114.9" cy="286.6" r="2.84"/>
<circle cx="121.9" cy="286.6" r="2.84"/>
<circle cx="128.9" cy="286.6" r="2.84"/>
<circle cx="135.9" cy="286.6" r="2.84"/>
<circle cx="142.9" cy="286.6" r="2.84"/>
<circle cx="149.9" cy="286.6" r="2.84"/>
<circle cx="73" cy="304.3" r="2.84"/>
<circle cx="80" cy="304.3" r="2.84"/>
<circle cx="87" cy="304.3" r="2.84"/>
<circle cx="94" cy="304.3" r="2.84"/>
<circle cx="101" cy="304.3" r="2.84"/>
<circle cx="107.9" cy="304.3" r="2.84"/>
<circle cx="114.9" cy="304.3" r="2.84"/>
<circle cx="121.9" cy="304.3" r="2.84"/>
<circle cx="128.9" cy="304.3" r="2.84"/>
<circle cx="135.9" cy="304.3" r="2.84"/>
<circle cx="142.9" cy="304.3" r="2.84"/>
<circle cx="149.9" cy="304.3" r="2.84"/>
<circle cx="72.1" cy="330.4" r="2.82"/>
<circle cx="73" cy="321.5" r="2.84"/>
<circle cx="80" cy="321.5" r="2.84"/>
<circle cx="87" cy="321.5" r="2.84"/>
<circle cx="94" cy="321.5" r="2.84"/>
<circle cx="101" cy="321.5" r="2.84"/>
<circle cx="103.5" cy="321.5" r="2.84"/>
<circle cx="107.9" cy="321.5" r="2.84"/>
<circle cx="110.5" cy="321.5" r="2.84"/>
<circle cx="114.9" cy="321.5" r="2.84"/>
<circle cx="117.5" cy="321.5" r="2.84"/>
<circle cx="121.9" cy="321.5" r="2.84"/>
<circle cx="128.9" cy="321.5" r="2.84"/>
<circle cx="135.9" cy="321.5" r="2.84"/>
<circle cx="142.9" cy="321.5" r="2.84"/>
<circle cx="149.9" cy="321.5" r="2.84"/>
</g>
<g fill="none" stroke="#840000" stroke-width=".3">
<path d="M504.6 73.3h3M508.4 74.3h3M514.1 73.3h3M521.7 73.3h3.1M529.3 74.3h3.1M534.4 74.3h3.1M382.7 165.1h3M393.4 165.1h3.1M421.4 191.8h3M467.7 197.8h3.1M477 190.7h2.3v5h-2.3zM485.5 197.8h3.1"/>
<path d="M421.4 215.9h3M411.2 259.8h3.1M429 260.4h3.1M209.9 317.5h3.1M462.7 311.2h3M416.3 325.8h3.1M491.4 389.5l.2-.2a.8 .8 0 0 1 .5 .8 .8 .8 0 0 1-.5 .7l-.4-.5zM493 389.2l-.3 1.1h.9M493.4 389.8v1M571.1 403h.6v.9M571.7 403.3l-.7 .3 .2 .3h.5"/>
</g>
<path d="M497.2 399.3l.9-.1 .2-.3-.1-.4-.2-.2h-.7l-.2 2 1-.1 .2-.5-.4-.4" fill="none" stroke="#840000" stroke-width=".41"/>
<g fill="none" stroke="#840000" stroke-width=".33">
<path d="M504.6 74.3h3M508.4 73.3h3M514.1 74.3h3M521.7 74.3h3.1M529.3 73.3h3.1M534.4 73.3h3.1M382.7 164.1h3M393.4 164.1h3.1M421.4 190.8h3M467.7 198.8h3.1M485.5 198.8h3.1M421.4 214.9h3"/>
<path d="M411.2 258.7h3.1M429 259.4h3.1M209.9 316.5h3.1M462.7 310.2h3M416.3 324.8h3.1"/>
</g>
<g fill="none" stroke="#008484" stroke-width=".26">
<path d="M401 97.4l.6-.1v-.3l-.6 .1 .1 .7h.5M401 86.6l.6-.1v-.3l-.6 .2 .1 .6h.5M401.2 81.5l.6-.1v-.3l-.6 .2 .1 .6h.5M401.2 91.7l.6-.1v-.3l-.6 .1 .1 .6h.5M443.4 88.4l.4 .5M443.8 88.1l-.5 .5M507.6 97l.8 .3-.8 .2M401.2 101.8l.6-.1v-.2l-.6 .1 .1 .6h.5M401.2 106.9l.6-.1v-.3l-.6 .2 .1 .6h.5M447.2 100.3l-.6-.1 .1-.6 .5-.1v1l-.3 .3-.3-.1M499 104v-.8l.3 .6 .2-.6v.8M499 106.2l.4-.1v-.3h-.4v.8"/>
<path d="M501.1 114.2v-.8l.2 .6 .3-.6v.8M502.4 113.4l-.5 .1 .5 .5-.2 .2-.3-.1M507.4 116h-.4v.2l.4 .4-.5 .1M507.7 115.9a.4 .4 0 0 1 .5 .4 .4 .4 0 0 1-.5 .4zM508.4 116.7l.2-.8 .3 .8M508.5 116.5h.3M527.7 109.6v.8M528 109.6h.4l.1 .2-.5 .6h.5M529.3 109.6a.36 .36 0 0 0-.5 .4 .36 .36 0 0 0 .5 .3M530.9 112.1v.8M531.2 112.2h.4v.1l-.4 .6h.4M531.5 103.2v.8"/>
<path d="M531.5 105.8v.8M531.6 114.7v.8M531.8 103.3l.3-.1 .2 .2-.5 .6h.5M531.9 105.8h.3l.1 .2-.5 .6h.5M532 114.7h.3l.1 .2-.4 .6h.4M500.7 122.3v.8l-.5-.8v.8M501.4 124.8h.4M501.6 124.8v.8M503.5 129.9a.4 .4 0 0 1 .5 .4 .4 .4 0 0 1-.5 .4zM504.2 130.7l.2-.8 .3 .8M504.3 130.5h.3M505 132.5a.36 .36 0 0 0-.5 .3 .36 .36 0 0 0 .5 .4"/>
<path d="M505.4 132.5v.7h.3M527.5 131.2v.6l-.3 .2M531.5 121v.8M531.5 123.6v.7M531.8 121.1l.4-.1 .1 .2-.5 .6h.5M531.9 123.6h.3l.1 .2-.5 .5h.5M533 128.6v.7l-.3 .1M433.6 140.9h-.4l-.2 .2 .1 .6h.5M433.6 156.8h-.4l-.2 .2 .1 .5h.5M434.1 141l.5-.1 .1 .8M434.1 156.9l.5-.1 .1 .8M434.1 140.5v1.2"/>
<path d="M434.1 156.3v1.3M526.6 155.2v.3h.8M527 155.3v.2M527.1 154.3v.6M530.1 150.2a.4 .4 0 0 1 .5 .4 .4 .4 0 0 1-.5 .4zM530.1 147.7a.4 .4 0 0 1 .5 .4 .4 .4 0 0 1-.5 .4zM530.8 151l.2-.8 .3 .8M530.8 148.5l.2-.8 .3 .8M530.9 150.8h.3M530.9 148.3h.3M344.8 235.9l.6-.1-.1-.2-.4-.1-.1 .2v.6h.5M211.8 240.8h.7"/>
<path d="M212.2 240.8v1.3M212.8 240.8l.4 .6 .4-.6M229.7 242.1h.7M230.8 240.8h.8l-.4 .5 .3 .1v.6l-.7-.1M293.5 240.1l.6-.1-.1-.3h-.4l-.1 .1v.7h.5M397.7 256.1l.4-.1v-.3h-.4v.8M405.5 256.1l.4-.1v-.3h-.4v.8M405.7 256.1l.3 .4M414.6 247.3v-.8l.3 .6 .2-.6v.8M428.2 246.5h.5l-.3 .3 .3 .2v.2h-.5M225.6 274.4a.64 .64 0 0 1 .7 .6 .64 .64 0 0 1-.7 .7zM225.6 277a.64 .64 0 0 1 .7 .6 .64 .64 0 0 1-.7 .6z"/>
<path d="M226.9 275.2h.9M226.9 277.7h.9M293.5 268.6l.6-.1-.1-.2-.4-.1-.1 .2v.6h.5M343.6 268.6l.6-.1v-.2l-.4-.1-.2 .2 .1 .6h.5M415.6 315.7v1.1l.3 .2 .5-.2v-1.1M428.8 315.7l-.4 .1-.2 .5v.6l.6 .1v-.7l-.4-.1-.2 .3"/>
</g>
<path d="M404.7 197.5h3.2z" fill="#840000" stroke="#840000" stroke-width=".51"/>
<g fill="#840000" stroke="#840000" stroke-width=".26">
<path d="M404.7 195.7l1.1 .6-.5 .5z"/>
<path d="M333.4 251.5h.8v.3h-.8z"/>
<path d="M333.4 249h.8v.2h-.8z"/>
<path d="M333.4 246.4h.8v.3h-.8z"/>
<path d="M333.4 243.9h.8v.2h-.8z"/>
<path d="M333.4 241.3h.8v.3h-.8z"/>
<path d="M333.4 238.8h.8v.3h-.8z"/>
<path d="M333.4 278.2h.8v.2h-.8z"/>
<path d="M333.4 275.6h.8v.3h-.8z"/>
<path d="M333.4 273.1h.8v.2h-.8z"/>
<path d="M333.4 270.6h.8v.2h-.8z"/>
<path d="M283.2 278.2h.9v.2h-.9z"/>
<path d="M283.2 275.6h.9v.3h-.9z"/>
<path d="M283.2 273.1h.9v.2h-.9z"/>
<path d="M283.2 270.6h.9v.2h-.9z"/>
<path d="M283.2 249.6h.9v.3h-.9z"/>
<path d="M283.2 247.1h.9v.2h-.9z"/>
<path d="M283.2 244.5h.9v.3h-.9z"/>
<path d="M283.2 242h.9v.2h-.9z"/>
<path d="M212.7 277.7l1.3 .1-.3 .4-.4 .1-.4-.2z"/>
<path d="M212.9 269.6l.7-.2 .4 .6h-1.3z"/>
<path d="M212.7 270h1.3v7.7h-1.3z"/>
<path d="M221.5 267.5h1.3v1.3h-1.3z"/>
<path d="M219.6 263.7l1.3 2.5h-2.6z"/>
<path d="M71.5 330.4l1-.4v.8z"/>
<circle cx="420.4" cy="148.1" r=".25"/>
<circle cx="420.4" cy="164" r=".25"/>
<circle cx="403.9" cy="316.4" r=".25"/>
<circle cx="403.9" cy="318.9" r=".25"/>
<circle cx="397.5" cy="321.5" r=".25"/>
<circle cx="410.2" cy="321.5" r=".25"/>
<circle cx="403.9" cy="324" r=".25"/>
<circle cx="403.9" cy="326.6" r=".25"/>
<circle cx="217" cy="269.4" r=".63"/>
<circle cx="73" cy="332.1" r=".28"/>
<circle cx="73" cy="328.6" r=".28"/>
</g>
<g fill="none" stroke="#840000" stroke-width="1.3">
<circle cx="386.7" cy="85.3" r="1.27"/>
<circle cx="386.7" cy="80.2" r="1.27"/>
<circle cx="386.7" cy="95.4" r="1.27"/>
<circle cx="386.7" cy="90.3" r="1.27"/>
<circle cx="432.4" cy="98.6" r="1.27"/>
<circle cx="432.4" cy="87.2" r="1.27"/>
<circle cx="432.4" cy="92.9" r="1.27"/>
<circle cx="432.4" cy="81.4" r="1.27"/>
<circle cx="386.7" cy="100.5" r="1.27"/>
<circle cx="386.7" cy="105.6" r="1.27"/>
<circle cx="432.4" cy="104.3" r="1.27"/>
<circle cx="432.4" cy="110" r="1.27"/>
</g>
<g fill="#ffffc2" stroke="#ffffc2" stroke-width=".26">
<path d="M419.1 143h10.2v10.2h-10.2z"/>
<path d="M419.1 158.9h10.2v10.2h-10.2z"/>
<path d="M396.2 313.9h15.3v15.2h-15.3z"/>
<path d="M208.9 243.4h20.3v63.5h-20.3z"/>
<path d="M304.8 329.1h10.2v10.2h-10.2z"/>
<path d="M288.3 329.1h10.1v10.2h-10.1z"/>
<path d="M321.3 329.1h10.2v10.2h-10.2z"/>
<path d="M337.8 329.1h10.2v10.2h-10.2z"/>
<path d="M337.8 305.6h10.2v10.2h-10.2z"/>
<path d="M321.3 305.6h10.2v10.2h-10.2z"/>
<path d="M304.8 305.6h10.2v10.2h-10.2z"/>
<path d="M288.3 305.6h10.1v10.2h-10.1z"/>
<path d="M416.6 248.5h10.1v6.9h-10.1z"/>
</g>
<path d="M490.2 85.9h50.8v80h-50.8zM476.1 191.9v2.6M480.2 191.9v2.6M211.9 268.8a1.9 1.9 0 0 1 2.1-.6 1.9 1.9 0 0 1 1.3 1.8v7.7a1.9 1.9 0 0 1-1.9 1.9 1.9 1.9 0 0 1-1.9-1.9v-7.8zM217 270v1.3l2.6 2.6M219.6 266.2v8.9M222.1 268.8v1.2l-2.5 2.6" fill="none" stroke="#840000" stroke-width=".51"/>
<path d="M505.1 140.5h-.8v.5l.7 .2 .1 .4-.3 .3-.6-.1M526.4 141l-.3-.3 .1-.2h.7v.4l-.5 .1-.3 .3 .3 .6h.3l.3-.3-.3-.6" fill="none" stroke="#008484" stroke-width=".3"/>
<g fill="none" stroke="#0000c2" stroke-width=".51" stroke-dasharray="1.1 1.1">
<path d="M28.6 66.2h332.1M360.7 66.2v149.9M377.2 76.4v44.4M410.2 76.4v45.1M418.5 76.4v43.8M418.5 76.4h36.2M464.8 62.4h102.3M567.1 62.4v158.1M370.2 134.8v41.3M377.2 120.8h33M418.5 120.2h36.2M447 134.8h-76.8"/>
<path d="M454.7 120.2v-43.8M370.2 176.1h76.8M447 176.1v-41.3M381.6 181.1v45.1M381.6 181.1h61M442.6 181.1v45.1M28.6 216.1v-149.9M360.7 216.1h-332.1M38.1 239.6h134.6M172.7 239.6v113.6M187.3 233.2h71.8M259.1 233.2v117.5"/>
<path d="M271.8 232.6h47.6M321.9 231.9h47.7M381.6 226.2h61.6M383.5 230v50.2M384.8 230h72.4M459.1 230.7v49.5M464.8 220.5v-158.1M464.8 220.5h102.3M271.8 259.9v-27.3M319.4 259.9h-47.6M319.4 259.9v-27.3M321.9 259.2v-27.3"/>
<path d="M369.6 259.2h-47.7M369.6 259.2v-27.3M271.8 261.2h47.6M321.9 261.2h47.7M271.1 291.6v61M271.8 288.5v-27.3M319.4 288.5h-47.6M319.4 288.5v-27.3M321.9 288.5v-27.3M369.6 288.5h-47.7M369.6 288.5v-27.3M369.6 291.6h-98.5"/>
<path d="M383.5 280.2h75.6M453.4 298h33M453.4 298v31.7M486.4 298v31.7M383.5 300.5h59.7M383.5 300.5v41.9M443.2 300.5v41.9M453.4 329.7h33M38.1 353.2v-113.6M172.7 353.2h-134.6M187.3 350.7v-117.5M259.1 350.7h-71.8"/>
<path d="M271.1 352.6h98.5M369.6 352.6v-61M383.5 342.4h59.7"/>
</g>
<path d="M202.6 311.3h12M202.6 311.3v24.8M202.6 336.1h12M214.6 336.1v-24.8" fill="none" stroke="#0000c2" stroke-width=".26" stroke-dasharray=".4 .4"/>
<path d="M377.2 76.4h33" fill="none" stroke="#0000c2" stroke-width=".51" stroke-dasharray="1.1 1.1 0 1.1"/>
<g fill="none" stroke="#008400" stroke-width=".26">
<path d="M50.2 76.4v102.8M75.6 76.4v102.8h3.8M101 76.4v102.8h3.8M126.4 76.4v102.8h3.8M151.8 76.4v121.9h3.8M177.2 76.4v121.9h3.8M202.6 76.4v121.9h3.8M228 76.4v102.8h3.8M253.4 76.4v102.8h3.8M278.8 76.4v102.8h3.8M304.2 76.4v102.8h3.8M329.6 76.4v104.1"/>
<path d="M500.4 78.9v1.9M506.1 71.3v-.6h3.8v.6M506.1 76.4v1.2h3.8v-1.2M508 70v.7M508 77.6v3.2M512.4 78.9v1.3h-4.4M515.6 70v1.3M515.6 76.4v4.4M519.4 78.9v1.3h-3.8M523.2 70v1.3M523.2 76.4v4.4M527 78.9v1.3h-3.8"/>
<path d="M530.9 70v1.3M530.9 76.4v4.4M530.9 78.9h6.9M535.9 70v1.3M535.9 76.4v2.5M41.3 83.4h301v.6M62.9 83.4v.6M62.9 91.6v.6M88.3 83.4v.6M88.3 91.6v.6M113.7 83.4v.6M113.7 91.6v.6"/>
<path d="M139.1 83.4v.6M139.1 91.6v.6M164.5 83.4v.6M164.5 91.6v.6M189.9 83.4v.6M189.9 91.6v.6M215.3 83.4v.6M215.3 91.6v.6M240.7 83.4v.6M240.7 91.6v.6M266.1 83.4v.6M266.1 91.6v.6"/>
<path d="M291.5 83.4v.6M291.5 91.6v.6M316.9 83.4v.6M316.9 91.6v.6M342.3 91.6v.6M390.5 95.4h3.2M546.1 96.1h1.9M546.1 88.4h1.9M546.1 91h1.9M546.1 93.5h1.9M41.3 109.4h301v.6M50.2 101.1h3.8"/>
<path d="M62.9 109.4v.6M62.9 117.6v.7M75.6 101.1h3.8M88.3 109.4v.6M88.3 117.6v.7M101 101.1h3.8M113.7 109.4v.6M113.7 117.6v.7M126.4 101.1h3.8M139.1 109.4v.6M139.1 117.6v.7M151.8 101.1h3.8"/>
<path d="M164.5 109.4v.6M164.5 117.6v.7M177.2 101.1h3.8M189.9 109.4v.6M189.9 117.6v.7M202.6 101.1h3.8M215.3 109.4v.6M215.3 117.6v.7M228 101.1h3.8M240.7 109.4v.6M240.7 117.6v.7M253.4 101.1h3.8"/>
<path d="M266.1 109.4v.6M266.1 117.6v.7M278.8 101.1h3.8M291.5 109.4v.6M291.5 117.6v.7M304.2 101.1h3.8M316.9 109.4v.6M316.9 117.6v.7M329.6 101.1h3.8M342.3 117.6v.7M483.9 103.7h1.2M483.9 106.2h1.2"/>
<path d="M483.9 116.4h1.2M483.9 113.8h1.2M546.1 101.1h1.9M546.1 110h1.9M546.1 103.7h1.9M546.1 106.2h1.9M546.1 117.6h1.9M546.1 112.6h1.9M546.1 115.1h1.9M41.3 135.4h301v.7M50.2 127.2h3.8M62.9 135.4v.7"/>
<path d="M75.6 127.2h3.8M88.3 135.4v.7M101 127.2h3.8M113.7 135.4v.7M126.4 127.2h3.8M139.1 135.4v.7M151.8 127.2h3.8M164.5 135.4v.7M177.2 127.2h3.8M189.9 135.4v.7M202.6 127.2h3.8M215.3 135.4v.7"/>
<path d="M228 127.2h3.8M240.7 135.4v.7M253.4 127.2h3.8M266.1 135.4v.7M278.8 127.2h3.8M291.5 135.4v.7M304.2 127.2h3.8M316.9 135.4v.7M329.6 127.2h3.8M483.9 139.2h1.2M483.9 125.3h1.2M483.9 122.7h1.2"/>
<path d="M483.9 132.9h1.2M483.9 130.3h1.2M546.1 139.2h1.9M546.1 134.2h1.9M546.1 126.5h1.9M546.1 131.6h1.9M546.1 136.7h1.9M546.1 124h1.9M546.1 121.5h1.9M546.1 129.1h1.9M50.2 153.2h3.8M62.9 143.7v.6"/>
<path d="M75.6 153.2h3.8M88.3 143.7v.6M101 153.2h3.8M113.7 143.7v.6M126.4 153.2h3.8M139.1 143.7v.6M151.8 153.2h3.8M164.5 143.7v.6M177.2 153.2h3.8M189.9 143.7v.6M202.6 153.2h3.8M215.3 143.7v.6"/>
<path d="M228 153.2h3.8M240.7 143.7v.6M253.4 153.2h3.8M266.1 143.7v.6M278.8 153.2h3.8M291.5 143.7v.6M304.2 153.2h3.8M316.9 143.7v.6M329.6 153.2h3.8M342.3 143.7v.6M382.9 154.5h1.3M384.2 148.8v-1.3h10.8v1.3"/>
<path d="M384.2 153.8v1.3M389.9 146.2v1.3M395 154.5h1.2M395 153.8v1.3M414.7 150.7h1.9M414.7 145.6h1.9M431.8 150.7h1.3M431.8 145.6h1.3M483.9 143h1.2M546.1 150.7h1.9M546.1 145.6h2.5M546.1 153.2h1.9"/>
<path d="M546.1 155.7h1.9M546.1 158.3h1.9M546.1 148.1h1.9M546.1 143h1.9M41.3 161.5h301v.6M48.3 179.2h5.7M62.9 169.7v.6h-2.6M62.9 161.5v.6M88.3 161.5v.6M88.3 169.7v.6M113.7 161.5v.6M113.7 169.7v.6"/>
<path d="M139.1 161.5v.6M139.1 169.7v.6M151.8 179.2h3.8M164.5 170.3v-.6h7.6v17.8h-7.6v1.9M164.5 161.5v.6M177.2 179.2h3.8M189.9 170.3v-.6h7.6v17.8h-7.6v1.9M189.9 161.5v.6M202.6 179.2h3.8M215.3 170.3v-.6h7.6v17.8h-7.6v1.9M215.3 161.5v.6M240.7 161.5v.6"/>
<path d="M240.7 169.7v.6M266.1 161.5v.6M266.1 169.7v.6M291.5 161.5v.6M291.5 169.7v.6M316.9 161.5v.6M316.9 169.7v.6M329.6 179.2h3.8M344.8 169.7h-2.5v.6M382.9 161.5h1.3M384.2 160.2v1.9M384.2 167.2v.6"/>
<path d="M395 160.2v1.9M395 167.2v.6M395 161.5h1.2M414.7 161.5h1.9M414.7 166.5h1.9M431.8 161.5h1.3M431.8 166.5h1.3M504.2 171v1.3M511.8 171v1.3M519.4 171v1.3M527 171v1.3M546.1 160.8h1.9"/>
<path d="M546.1 163.4h1.9M400 195.1h1.3M411.5 195.1h19M422.9 187.5v1.3M422.9 193.8v1.3M469.3 191.9v3.8M469.3 193.2h5M478.2 185.6v2.5M478.2 198.3v3.8M482 193.2h5M487 191.9v3.8M404.5 210.4h3.8"/>
<path d="M406.4 204v6.4M415.9 210.4h14.6M419.1 210.4v2.5M419.1 218v1.2M422.9 210.4v2.5M422.9 218v1.2M469.3 200.8v1.3h17.7v-1.3M338.5 238.9h1.9M417.8 238.3h-5.1v18.4M425.4 238.3h5.1v19M68.6 256.7v54.6h81.3M68.6 259.2h81.3"/>
<path d="M234.3 245.9h11.4M234.3 258.6h2.6M236.2 245.9v2.6h-1.9M288.3 242.1h1.9M288.3 249.7h1.9M288.3 244.6h1.9M288.3 247.2h1.9M338.5 249.1h1.9M338.5 246.5h1.9M338.5 251.6h1.9M338.5 244h1.9M338.5 241.5h1.9"/>
<path d="M396.9 250.4h1.2M403.2 250.4h10.8M407 248.5v3.1M407 256.7v1.3M421.6 258v9.5M429.3 250.4h8.8M68.6 276.4h81.3M73 271.9h83.8v53.4h-83.8M234.3 263.7h2.6M234.3 275.1h4.5M236.2 275.1v2.6h-1.9M288.3 270.7h1.9"/>
<path d="M288.3 278.3h1.9M288.3 273.2h1.9M288.3 275.8h1.9M338.5 270.7h1.9M338.5 278.3h1.9M338.5 273.2h1.9M338.5 275.8h1.9M412.7 261.8v3.8h17.8v-3.2M68.6 294.2h81.3M73 290.4h83.8M73 281.5v1.2M73 299.3v1.2"/>
<path d="M80 281.5v1.2M80 299.3v1.2M87 281.5v1.2M87 299.3v1.2M94 281.5v1.2M94 299.3v1.2M101 281.5v1.2M101 299.3v1.2M107.9 281.5v1.2M107.9 299.3v1.2M114.9 281.5v1.2M114.9 299.3v1.2"/>
<path d="M121.9 281.5v1.2M121.9 299.3v1.2M128.9 281.5v1.2M128.9 299.3v1.2M135.9 281.5v1.2M135.9 299.3v1.2M142.9 281.5v1.2M142.9 299.3v1.2M149.9 281.5v1.2M149.9 299.3v1.2M234.3 285.3h6.4M234.3 282.7h4.5"/>
<path d="M236.2 282.7v2.6M245.7 285.3h1.9M293.4 299.9v3.2M73 308.1h83.8M73 316.4v1.3M80 316.4v1.3M87 316.4v1.3M94 316.4v1.3M101 317h2.5v.7M101 316.4v1.3M107.9 317h2.6v.7M107.9 316.4v1.3"/>
<path d="M114.9 317h2.6v.7M114.9 316.4v1.3M121.9 316.4v1.3M128.9 316.4v1.3M135.9 316.4v1.3M142.9 316.4v1.3M149.9 316.4v1.3M206.4 313.2h5.1M211.5 319.6v1.2h-5.1v1.3M211.5 312v2.5M216.5 312v1.2h2.6M219.1 312v2.5"/>
<path d="M284.5 310.7h1.2M293.4 318.3v1.3h49.5v-1.3M293.4 301.8h49.5v1.3M301 310.7h1.3M309.9 301.8v1.3M309.9 318.3v2.5M317.5 310.7h1.3M326.4 301.8v1.3M326.4 318.3v1.3M334 310.7h1.3M398.8 306.9h2.5v1.9M407.7 306.9h-1.3v1.9"/>
<path d="M412.7 306.9h1.3M459.1 306.9h7.6M464.2 313.2v1.3h-5.1v1.3M464.2 306.9v1.2M474.3 306.9h.7M56.5 330.4h1.9M63.5 330.4h1.9M64.8 330.4v1.9M64.8 337.4v2.5h8.2M73 335.4v7M284.5 334.2h1.2M293.4 325.3h49.5v1.3"/>
<path d="M293.4 324v2.6M301 334.2h1.3M309.9 325.3v1.3M317.5 334.2h1.3M326.4 325.3v1.3M334 334.2h1.3M388.6 321.5h2.6M401.3 334.2v1.2h-2.5M406.4 334.2v1.2h1.3M412.7 335.4h1.3M416.6 321.5h3.8M417.8 321.5v1.2"/>
<path d="M417.8 327.8v1.3M293.4 341.8v1.3h49.5v-1.3M309.9 341.8v2.5M326.4 341.8v1.3"/>
</g>
<g fill="none" stroke="#0000c2" stroke-width=".51">
<path d="M408.2 116.8a.65 .65 0 0 0-1 .2v.4a.77 .77 0 0 1 1 .5l-.5 .5-.7-.2M449.5 116.7l-.5 2.3a.73 .73 0 0 1-.9 .1M449.5 116.8a.85 .85 0 0 0-1.3 .3l-.1 .8 .2 .3h1M451.5 116.8a.65 .65 0 0 0-1 .2l.1 .4a.77 .77 0 0 1 .9 .5l-.4 .5-.8-.2M402.8 138.4a.62 .62 0 0 0-1 .3l.1 .3a.73 .73 0 0 1 .9 .6l-.5 .3-.6-.1M414 183.3l-.1 1.6a.68 .68 0 0 0 1-.1M415 183.3l-.2 1.7M416.3 183.3l-.2 1.7M416.4 182.5l-.1 .2M417.1 183.3h1M417.6 182.5l-.3 2.1 .1 .3 .5 .1M357.6 255.3a.61 .61 0 0 1 1.1 .1l-.2 1.4"/>
<path d="M361 255.1l-.4 2.3a.73 .73 0 0 1-1 .1M361 255.2a.85 .85 0 0 0-1.3 .4v.7l.1 .4h1M448 274.8l-.3 1.7M448.7 274.8l-.5 .1-.3 .4M450.6 274.9a.85 .85 0 0 0-1.3 .4v.9l.4 .3 .7-.2M451.7 274.8l-.1 1.5a.7 .7 0 0 0 1-.1M452.8 274.8l-.2 1.7M454 274.8l-.2 1.7M454.1 273.9v.3M454.8 274.8h1M455.3 273.9l-.3 2.2 .1 .2 .5 .2M482.7 319.6a.64 .64 0 0 1 1 .1l-.1 1.3"/>
<path d="M436.9 333.1a1.21 1.21 0 0 1 1.3 .7 1.21 1.21 0 0 1-.4 1.5l-.6 .4h-.7zM438.7 338.5a.64 .64 0 0 1 1.1 .1l-.2 1.4M481.2 323.9a.64 .64 0 0 1 1.1 .1l-.2 1.4"/>
</g>
<g fill="none" stroke="#0000c2" stroke-width=".76">
<path d="M298.4 199.4l1.7 2.6M300.5 199.4l-2.4 2.6M538.5 209.8l.4-.2h.7l.3 .2 .2 .4-.3 1.9M540 210.5l-1.3 .2a.76 .76 0 0 0-.6 .6 .76 .76 0 0 0 .4 .8l1.3-.1M542.1 208.3l-.4 3.3 .5 .5M128.7 249l-.4 2.5M128.8 247.7l-.2 .2 .2 .2 .2-.2-.2-.2v.4M130.1 249l1.7 2.5M132.1 249l-2.3 2.5M316.4 254.7l-.3 2.5M317.5 254.7a1.19 1.19 0 0 0-1.2 .7M317.2 283.5a.91 .91 0 0 0-1.5 .5l.1 .3 .9 .2 .5 .6-.3 .5-.3 .2-1.1-.2"/>
<path d="M367.4 283.5a.91 .91 0 0 0-1.5 .5l.1 .3 .9 .2 .5 .6-.3 .5-.4 .2-1-.2M244.9 344.2l-.3 2.6M246 344.2a1.19 1.19 0 0 0-1.1 .7"/>
</g>
<g fill="none" stroke="#0000c2" stroke-width=".26">
<path d="M404 250.9h.3M404.7 250.9l-.3 .2 .1 .3 .2-.1M448.1 268.2l.3-.2h-.3l-.1 .4 .4 .1M449.3 269.1h.5l-.2 .6h-.3zM449.4 267.7l-.1 .8M449.7 268.1l.3-.1v.5M449.7 268v.5M450.1 269.3v.4h.3M450.4 268l.3 .1-.1 .4h-.3M450.4 268l-.1 .7M450.4 269.3v.5M450.7 269.3h.3"/>
<path d="M450.8 269l-.1 .7 .2 .1M451.1 268v.5l.3-.1M451.2 269.7h.3v-.4h-.3v.7M451.4 268v.5M451.7 268h.3M451.8 267.7l-.1 .7 .2 .1M451.9 269.3v.4h.3M452.2 269.3v.5M452.5 269.3h.3M452.7 269l-.1 .7 .1 .1M96.4 335.3h.3M96.5 335l-.1 .7 .2 .1"/>
<path d="M97 336.6h.3M97.2 336.3l-.1 .7 .1 .1M98.6 335.1a.34 .34 0 0 0-.5 .3 .34 .34 0 0 0 .5 .3l-.1-.2M99 335.3l.3 .1-.1 .4h-.2l-.1-.2 .4-.1M99.2 336.4a.34 .34 0 0 0-.5 .2 .34 .34 0 0 0 .5 .4v-.3h-.1M99.5 335.3h.3M99.6 336.6h.3l-.1 .5M99.7 335l-.1 .7 .2 .1M99.9 336.7l-.4 .2v.1h.3M100 335.6l.4-.3-.4 .1v.4h.3M100.2 336.6h.3M100.3 336.3l-.1 .7 .2 .1"/>
<path d="M100.6 336.8l.4-.2h-.3l-.1 .4h.3M208.8 331.6h-.3l-.3 .2 .2 .6h.4M208.8 331.2v1.2M232.8 326.2h-.3l-.1 .2 .3 .2v.2l-.4 .1M233.1 326.5h.3v.4M233.2 326.2l-.1 .7M233.2 330.2v.5l.3-.1M233.5 330.2v.5M233.6 328.8a.34 .34 0 0 0-.5 .2 .34 .34 0 0 0 .5 .4M233.7 327.5h-.5v.2l.4 .3-.5 .2M233.8 326.4v.5M233.9 326.2h-.1"/>
<path d="M233.9 330v.7M234 327.8l.2-.1v.5M234 327.4l-.1 .8M234.1 326.7l.4-.2h-.3l-.1 .3 .3 .1M234.3 330v.7M234.5 329l.3 .1-.1 .3h-.3M234.5 328.9l-.1 .8M234.6 327.7v.5M234.7 327.4v.1M234.9 326.2v.7M234.9 327.9l.4-.2h-.3l-.1 .4 .4 .1M235.2 328.9l-.1 .6"/>
<path d="M235.2 328.7v.1M235.3 330l.1 .7 .3-.1v-.6M235.6 326.5h-.3l-.1 .3 .3 .1M235.6 329h.2v.5M235.6 328.9l-.1 .6M235.6 326.2l-.1 .7M235.7 327.4v.8M236 330.7l.3-.1v-.4l-.2 .1-.1 .7M236.4 327.4l-.1 .8h-.3l.1-.4 .3-.1M433.6 327.4a.39 .39 0 0 1 .4 .5 .39 .39 0 0 1-.5 .3zM434.3 327.7h.3v.5h-.3v-.3h.3M434.4 328.7a.39 .39 0 0 1 .4 .4 .39 .39 0 0 1-.5 .4z"/>
<path d="M434.9 327.7h.3M435.1 327.4l-.1 .7 .1 .1M435.2 329h.3l-.1 .5-.3-.1v-.2l.4-.1M435.5 327.7l.3 .1-.1 .4h-.2l-.1-.3h.4M435.7 328.9h.3M435.9 328.7l-.1 .7 .2 .1M436.3 329h.3l-.1 .5h-.2v-.3l.3-.1"/>
<circle cx="97.1" cy="335.6" r=".26"/>
<circle cx="97.7" cy="336.8" r=".26"/>
</g>
<g fill="#008400" stroke="#008400" stroke-width=".26">
<circle cx="121.9" cy="311.3" r=".51"/>
<circle cx="329.6" cy="127.2" r=".51"/>
<circle cx="101" cy="276.4" r=".51"/>
<circle cx="309.9" cy="325.3" r=".51"/>
<circle cx="94" cy="276.4" r=".51"/>
<circle cx="326.4" cy="325.3" r=".51"/>
<circle cx="108" cy="276.4" r=".51"/>
<circle cx="114.9" cy="276.4" r=".51"/>
<circle cx="121.9" cy="276.4" r=".51"/>
<circle cx="128.9" cy="276.4" r=".51"/>
<circle cx="135.9" cy="276.4" r=".51"/>
<circle cx="430.5" cy="250.4" r=".51"/>
<circle cx="142.9" cy="276.4" r=".51"/>
<circle cx="88.3" cy="83.4" r=".51"/>
<circle cx="202.6" cy="127.2" r=".51"/>
<circle cx="326.4" cy="301.8" r=".51"/>
<circle cx="326.4" cy="343.1" r=".51"/>
<circle cx="73" cy="259.2" r=".51"/>
<circle cx="80" cy="259.2" r=".51"/>
<circle cx="326.4" cy="319.6" r=".51"/>
<circle cx="142.9" cy="311.3" r=".51"/>
<circle cx="215.3" cy="135.4" r=".51"/>
<circle cx="87" cy="259.2" r=".51"/>
<circle cx="309.9" cy="319.6" r=".51"/>
<circle cx="309.9" cy="343.1" r=".51"/>
<circle cx="135.9" cy="311.3" r=".51"/>
<circle cx="94" cy="259.2" r=".51"/>
<circle cx="101" cy="259.2" r=".51"/>
<circle cx="114.9" cy="259.2" r=".51"/>
<circle cx="293.4" cy="325.3" r=".51"/>
<circle cx="128.9" cy="311.3" r=".51"/>
<circle cx="121.9" cy="259.2" r=".51"/>
<circle cx="128.9" cy="259.2" r=".51"/>
<circle cx="135.9" cy="259.2" r=".51"/>
<circle cx="142.9" cy="259.2" r=".51"/>
<circle cx="68.6" cy="276.4" r=".51"/>
<circle cx="73" cy="276.4" r=".51"/>
<circle cx="88.3" cy="161.5" r=".51"/>
<circle cx="80" cy="276.4" r=".51"/>
<circle cx="293.4" cy="301.8" r=".51"/>
<circle cx="62.9" cy="161.5" r=".51"/>
<circle cx="309.9" cy="301.8" r=".51"/>
<circle cx="87" cy="276.4" r=".51"/>
<circle cx="114.9" cy="294.2" r=".51"/>
<circle cx="240.7" cy="135.4" r=".51"/>
<circle cx="73" cy="339.9" r=".51"/>
<circle cx="316.9" cy="135.4" r=".51"/>
<circle cx="68.6" cy="259.2" r=".51"/>
<circle cx="142.9" cy="294.2" r=".51"/>
<circle cx="135.9" cy="294.2" r=".51"/>
<circle cx="128.9" cy="294.2" r=".51"/>
<circle cx="121.9" cy="294.2" r=".51"/>
<circle cx="421.6" cy="265.6" r=".51"/>
<circle cx="422.9" cy="210.4" r=".51"/>
<circle cx="508" cy="70.7" r=".51"/>
<circle cx="108" cy="294.2" r=".51"/>
<circle cx="419.1" cy="210.4" r=".51"/>
<circle cx="101" cy="294.2" r=".51"/>
<circle cx="422.9" cy="195.1" r=".51"/>
<circle cx="50.2" cy="101.1" r=".51"/>
<circle cx="139.1" cy="83.4" r=".51"/>
<circle cx="459.1" cy="314.5" r=".51"/>
<circle cx="88.3" cy="109.4" r=".51"/>
<circle cx="291.5" cy="135.4" r=".51"/>
<circle cx="113.7" cy="109.4" r=".51"/>
<circle cx="156.8" cy="308.1" r=".51"/>
<circle cx="156.8" cy="290.4" r=".51"/>
<circle cx="316.9" cy="83.4" r=".51"/>
<circle cx="240.7" cy="83.4" r=".51"/>
<circle cx="75.6" cy="127.2" r=".51"/>
<circle cx="164.5" cy="109.4" r=".51"/>
<circle cx="395" cy="161.5" r=".51"/>
<circle cx="189.9" cy="109.4" r=".51"/>
<circle cx="412.7" cy="250.4" r=".51"/>
<circle cx="384.2" cy="161.5" r=".51"/>
<circle cx="215.3" cy="109.4" r=".51"/>
<circle cx="139.1" cy="135.4" r=".51"/>
<circle cx="73" cy="294.2" r=".51"/>
<circle cx="508" cy="80.2" r=".51"/>
<circle cx="202.6" cy="101.1" r=".51"/>
<circle cx="266.1" cy="135.4" r=".51"/>
<circle cx="228" cy="101.1" r=".51"/>
<circle cx="228" cy="127.2" r=".51"/>
<circle cx="530.9" cy="78.9" r=".51"/>
<circle cx="253.4" cy="101.1" r=".51"/>
<circle cx="253.4" cy="127.2" r=".51"/>
<circle cx="177.2" cy="127.2" r=".51"/>
<circle cx="508" cy="77.6" r=".51"/>
<circle cx="278.8" cy="101.1" r=".51"/>
<circle cx="278.8" cy="127.2" r=".51"/>
<circle cx="304.2" cy="101.1" r=".51"/>
<circle cx="469.3" cy="193.2" r=".51"/>
<circle cx="304.2" cy="127.2" r=".51"/>
<circle cx="68.6" cy="294.2" r=".51"/>
<circle cx="329.6" cy="101.1" r=".51"/>
<circle cx="177.2" cy="101.1" r=".51"/>
<circle cx="80" cy="294.2" r=".51"/>
<circle cx="523.2" cy="80.2" r=".51"/>
<circle cx="151.8" cy="127.2" r=".51"/>
<circle cx="151.8" cy="101.1" r=".51"/>
<circle cx="266.1" cy="83.4" r=".51"/>
<circle cx="515.6" cy="80.2" r=".51"/>
<circle cx="126.4" cy="127.2" r=".51"/>
<circle cx="126.4" cy="101.1" r=".51"/>
<circle cx="535.9" cy="78.9" r=".51"/>
<circle cx="87" cy="294.2" r=".51"/>
<circle cx="291.5" cy="83.4" r=".51"/>
<circle cx="101" cy="127.2" r=".51"/>
<circle cx="101" cy="101.1" r=".51"/>
<circle cx="94" cy="294.2" r=".51"/>
<circle cx="135.9" cy="308.1" r=".51"/>
<circle cx="164.5" cy="169.7" r=".51"/>
<circle cx="149.9" cy="308.1" r=".51"/>
<circle cx="406.4" cy="210.4" r=".51"/>
<circle cx="316.9" cy="109.4" r=".51"/>
<circle cx="149.9" cy="290.4" r=".51"/>
<circle cx="149.9" cy="271.9" r=".51"/>
<circle cx="240.7" cy="109.4" r=".51"/>
<circle cx="75.6" cy="101.1" r=".51"/>
<circle cx="142.9" cy="325.3" r=".51"/>
<circle cx="142.9" cy="308.1" r=".51"/>
<circle cx="139.1" cy="109.4" r=".51"/>
<circle cx="50.2" cy="127.2" r=".51"/>
<circle cx="142.9" cy="290.4" r=".51"/>
<circle cx="142.9" cy="271.9" r=".51"/>
<circle cx="135.9" cy="325.3" r=".51"/>
<circle cx="149.9" cy="325.3" r=".51"/>
<circle cx="135.9" cy="290.4" r=".51"/>
<circle cx="135.9" cy="271.9" r=".51"/>
<circle cx="128.9" cy="325.3" r=".51"/>
<circle cx="128.9" cy="308.1" r=".51"/>
<circle cx="128.9" cy="290.4" r=".51"/>
<circle cx="236.2" cy="282.7" r=".51"/>
<circle cx="128.9" cy="271.9" r=".51"/>
<circle cx="236.2" cy="275.1" r=".51"/>
<circle cx="121.9" cy="325.3" r=".51"/>
<circle cx="113.7" cy="83.4" r=".51"/>
<circle cx="291.5" cy="109.4" r=".51"/>
<circle cx="121.9" cy="308.1" r=".51"/>
<circle cx="121.9" cy="290.4" r=".51"/>
<circle cx="266.1" cy="109.4" r=".51"/>
<circle cx="114.9" cy="311.3" r=".51"/>
<circle cx="329.6" cy="153.2" r=".51"/>
<circle cx="75.6" cy="153.2" r=".51"/>
<circle cx="464.2" cy="306.9" r=".51"/>
<circle cx="101" cy="153.2" r=".51"/>
<circle cx="126.4" cy="153.2" r=".51"/>
<circle cx="202.6" cy="153.2" r=".51"/>
<circle cx="113.7" cy="135.4" r=".51"/>
<circle cx="164.5" cy="83.4" r=".51"/>
<circle cx="407" cy="250.4" r=".51"/>
<circle cx="228" cy="153.2" r=".51"/>
<circle cx="114.9" cy="271.9" r=".51"/>
<circle cx="253.4" cy="153.2" r=".51"/>
<circle cx="108" cy="259.2" r=".51"/>
<circle cx="278.8" cy="153.2" r=".51"/>
<circle cx="101" cy="271.9" r=".51"/>
<circle cx="304.2" cy="153.2" r=".51"/>
<circle cx="121.9" cy="271.9" r=".51"/>
<circle cx="206.4" cy="320.8" r=".51"/>
<circle cx="211.5" cy="313.2" r=".51"/>
<circle cx="62.9" cy="109.4" r=".51"/>
<circle cx="215.3" cy="169.7" r=".51"/>
<circle cx="236.2" cy="285.3" r=".51"/>
<circle cx="202.6" cy="179.2" r=".51"/>
<circle cx="151.8" cy="179.2" r=".51"/>
<circle cx="177.2" cy="179.2" r=".51"/>
<circle cx="189.9" cy="169.7" r=".51"/>
<circle cx="88.3" cy="135.4" r=".51"/>
<circle cx="62.9" cy="170.3" r=".51"/>
<circle cx="62.9" cy="135.4" r=".51"/>
<circle cx="177.2" cy="153.2" r=".51"/>
<circle cx="151.8" cy="153.2" r=".51"/>
<circle cx="50.2" cy="179.2" r=".51"/>
<circle cx="117.5" cy="325.3" r=".51"/>
<circle cx="80" cy="325.3" r=".51"/>
<circle cx="478.2" cy="202.1" r=".51"/>
<circle cx="80" cy="308.1" r=".51"/>
<circle cx="80" cy="290.4" r=".51"/>
<circle cx="487" cy="193.2" r=".51"/>
<circle cx="80" cy="271.9" r=".51"/>
<circle cx="73" cy="325.3" r=".51"/>
<circle cx="342.3" cy="169.7" r=".51"/>
<circle cx="215.3" cy="161.5" r=".51"/>
<circle cx="329.6" cy="179.2" r=".51"/>
<circle cx="108" cy="317" r=".51"/>
<circle cx="114.9" cy="317" r=".51"/>
<circle cx="189.9" cy="83.4" r=".51"/>
<circle cx="50.2" cy="153.2" r=".51"/>
<circle cx="101" cy="317" r=".51"/>
<circle cx="189.9" cy="161.5" r=".51"/>
<circle cx="164.5" cy="161.5" r=".51"/>
<circle cx="62.9" cy="83.4" r=".51"/>
<circle cx="395" cy="154.5" r=".51"/>
<circle cx="384.2" cy="154.5" r=".51"/>
<circle cx="389.9" cy="147.5" r=".51"/>
<circle cx="73" cy="311.3" r=".51"/>
<circle cx="80" cy="311.3" r=".51"/>
<circle cx="87" cy="311.3" r=".51"/>
<circle cx="94" cy="311.3" r=".51"/>
<circle cx="215.3" cy="83.4" r=".51"/>
<circle cx="101" cy="311.3" r=".51"/>
<circle cx="108" cy="311.3" r=".51"/>
<circle cx="113.7" cy="161.5" r=".51"/>
<circle cx="189.9" cy="135.4" r=".51"/>
<circle cx="114.9" cy="325.3" r=".51"/>
<circle cx="114.9" cy="308.1" r=".51"/>
<circle cx="316.9" cy="161.5" r=".51"/>
<circle cx="114.9" cy="290.4" r=".51"/>
<circle cx="240.7" cy="161.5" r=".51"/>
<circle cx="139.1" cy="161.5" r=".51"/>
<circle cx="110.5" cy="325.3" r=".51"/>
<circle cx="219.1" cy="313.2" r=".51"/>
<circle cx="108" cy="325.3" r=".51"/>
<circle cx="108" cy="308.1" r=".51"/>
<circle cx="108" cy="290.4" r=".51"/>
<circle cx="236.2" cy="245.9" r=".51"/>
<circle cx="108" cy="271.9" r=".51"/>
<circle cx="103.5" cy="325.3" r=".51"/>
<circle cx="101" cy="325.3" r=".51"/>
<circle cx="94" cy="308.1" r=".51"/>
<circle cx="87" cy="271.9" r=".51"/>
<circle cx="87" cy="290.4" r=".51"/>
<circle cx="87" cy="308.1" r=".51"/>
<circle cx="87" cy="325.3" r=".51"/>
<circle cx="266.1" cy="161.5" r=".51"/>
<circle cx="94" cy="271.9" r=".51"/>
<circle cx="291.5" cy="161.5" r=".51"/>
<circle cx="94" cy="290.4" r=".51"/>
<circle cx="164.5" cy="135.4" r=".51"/>
<circle cx="94" cy="325.3" r=".51"/>
<circle cx="101" cy="290.4" r=".51"/>
<circle cx="64.8" cy="330.4" r=".51"/>
<circle cx="417.8" cy="321.5" r=".51"/>
<circle cx="101" cy="308.1" r=".51"/>
</g>
<path d="M233.7 301.2l1.2 1.2M233.7 303.7l1.2 1.2M234.9 301.2l-1.2 1.2M234.9 303.7l-1.2 1.2" fill="none" stroke="#000084" stroke-width=".26"/>
<use href="#words"/>
</svg>
